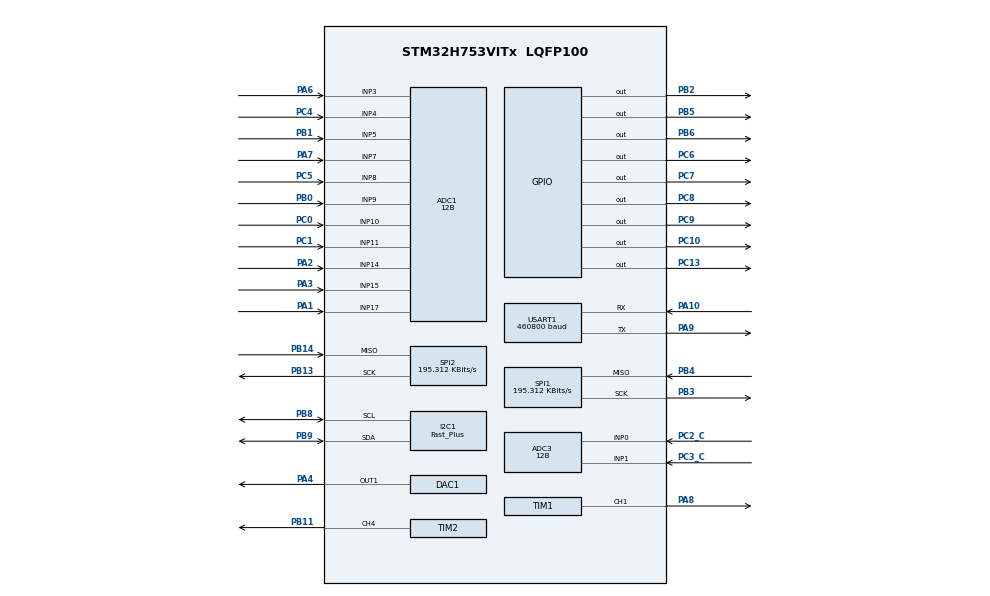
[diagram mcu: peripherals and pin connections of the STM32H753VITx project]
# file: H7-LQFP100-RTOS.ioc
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ADC1.Channel-0\#ChannelRegularConversion=ADC_CHANNEL_3
ADC1.Channel-1\#ChannelRegularConversion=ADC_CHANNEL_4
ADC1.Channel-10\#ChannelRegularConversion=ADC_CHANNEL_17
ADC1.Channel-2\#ChannelRegularConversion=ADC_CHANNEL_5
ADC1.Channel-3\#ChannelRegularConversion=ADC_CHANNEL_7
ADC1.Channel-4\#ChannelRegularConversion=ADC_CHANNEL_8
ADC1.Channel-5\#ChannelRegularConversion=ADC_CHANNEL_9
ADC1.Channel-6\#ChannelRegularConversion=ADC_CHANNEL_10
ADC1.Channel-7\#ChannelRegularConversion=ADC_CHANNEL_11
ADC1.Channel-8\#ChannelRegularConversion=ADC_CHANNEL_14
ADC1.Channel-9\#ChannelRegularConversion=ADC_CHANNEL_15
ADC1.ClockPrescaler=ADC_CLOCK_ASYNC_DIV2
ADC1.ClockPrescalerADC3=ADC_CLOCK_ASYNC_DIV2
ADC1.ContinuousConvMode=ENABLE
ADC1.ConversionDataManagement=ADC_CONVERSIONDATA_DMA_CIRCULAR
ADC1.NbrOfConversion=11
ADC1.NbrOfConversionFlag=1
ADC1.OffsetNumber-0\#ChannelRegularConversion=ADC_OFFSET_NONE
ADC1.OffsetNumber-1\#ChannelRegularConversion=ADC_OFFSET_NONE
ADC1.OffsetNumber-10\#ChannelRegularConversion=ADC_OFFSET_NONE
ADC1.OffsetNumber-2\#ChannelRegularConversion=ADC_OFFSET_NONE
ADC1.OffsetNumber-3\#ChannelRegularConversion=ADC_OFFSET_NONE
ADC1.OffsetNumber-4\#ChannelRegularConversion=ADC_OFFSET_NONE
ADC1.OffsetNumber-5\#ChannelRegularConversion=ADC_OFFSET_NONE
ADC1.OffsetNumber-6\#ChannelRegularConversion=ADC_OFFSET_NONE
ADC1.OffsetNumber-7\#ChannelRegularConversion=ADC_OFFSET_NONE
ADC1.OffsetNumber-8\#ChannelRegularConversion=ADC_OFFSET_NONE
ADC1.OffsetNumber-9\#ChannelRegularConversion=ADC_OFFSET_NONE
ADC1.OffsetSignedSaturation-0\#ChannelRegularConversion=DISABLE
ADC1.Overrun=ADC_OVR_DATA_OVERWRITTEN
ADC1.Rank-0\#ChannelRegularConversion=1
ADC1.Rank-1\#ChannelRegularConversion=2
ADC1.Rank-10\#ChannelRegularConversion=11
ADC1.Rank-2\#ChannelRegularConversion=3
ADC1.Rank-3\#ChannelRegularConversion=4
ADC1.Rank-4\#ChannelRegularConversion=5
ADC1.Rank-5\#ChannelRegularConversion=6
ADC1.Rank-6\#ChannelRegularConversion=7
ADC1.Rank-7\#ChannelRegularConversion=8
ADC1.Rank-8\#ChannelRegularConversion=9
ADC1.Rank-9\#ChannelRegularConversion=10
ADC1.Resolution=ADC_RESOLUTION_12B
ADC1.SamplingTime-0\#ChannelRegularConversion=ADC_SAMPLETIME_810CYCLES_5
ADC1.SamplingTime-1\#ChannelRegularConversion=ADC_SAMPLETIME_810CYCLES_5
ADC1.SamplingTime-10\#ChannelRegularConversion=ADC_SAMPLETIME_810CYCLES_5
ADC1.SamplingTime-2\#ChannelRegularConversion=ADC_SAMPLETIME_810CYCLES_5
ADC1.SamplingTime-3\#ChannelRegularConversion=ADC_SAMPLETIME_810CYCLES_5
ADC1.SamplingTime-4\#ChannelRegularConversion=ADC_SAMPLETIME_810CYCLES_5
ADC1.SamplingTime-5\#ChannelRegularConversion=ADC_SAMPLETIME_810CYCLES_5
ADC1.SamplingTime-6\#ChannelRegularConversion=ADC_SAMPLETIME_810CYCLES_5
ADC1.SamplingTime-7\#ChannelRegularConversion=ADC_SAMPLETIME_810CYCLES_5
ADC1.SamplingTime-8\#ChannelRegularConversion=ADC_SAMPLETIME_810CYCLES_5
ADC1.SamplingTime-9\#ChannelRegularConversion=ADC_SAMPLETIME_810CYCLES_5
ADC1.master=1
ADC3.Channel-0\#ChannelRegularConversion=ADC_CHANNEL_TEMPSENSOR
ADC3.Channel-1\#ChannelRegularConversion=ADC_CHANNEL_VREFINT
ADC3.Channel-2\#ChannelRegularConversion=ADC_CHANNEL_0
ADC3.Channel-3\#ChannelRegularConversion=ADC_CHANNEL_1
ADC3.ClockPrescalerADC3=ADC_CLOCK_ASYNC_DIV2
ADC3.ContinuousConvMode=ENABLE
ADC3.ConversionDataManagement=ADC_CONVERSIONDATA_DMA_CIRCULAR
ADC3.NbrOfConversion=4
ADC3.NbrOfConversionFlag=1
ADC3.OffsetNumber-0\#ChannelRegularConversion=ADC_OFFSET_NONE
ADC3.OffsetNumber-1\#ChannelRegularConversion=ADC_OFFSET_NONE
ADC3.OffsetNumber-2\#ChannelRegularConversion=ADC_OFFSET_NONE
ADC3.OffsetNumber-3\#ChannelRegularConversion=ADC_OFFSET_NONE
ADC3.OffsetSignedSaturation-0\#ChannelRegularConversion=DISABLE
ADC3.Overrun=ADC_OVR_DATA_OVERWRITTEN
ADC3.Rank-0\#ChannelRegularConversion=1
ADC3.Rank-1\#ChannelRegularConversion=2
ADC3.Rank-2\#ChannelRegularConversion=3
ADC3.Rank-3\#ChannelRegularConversion=4
ADC3.Resolution=ADC_RESOLUTION_12B
ADC3.SamplingTime-0\#ChannelRegularConversion=ADC_SAMPLETIME_810CYCLES_5
ADC3.SamplingTime-1\#ChannelRegularConversion=ADC_SAMPLETIME_810CYCLES_5
ADC3.SamplingTime-2\#ChannelRegularConversion=ADC_SAMPLETIME_810CYCLES_5
ADC3.SamplingTime-3\#ChannelRegularConversion=ADC_SAMPLETIME_810CYCLES_5
DAC1.DAC_Channel-DAC_OUT1=DAC_CHANNEL_1
DAC1.DAC_Trigger-DAC_OUT1=DAC_TRIGGER_T2_TRGO
Dma.ADC1.0.Direction=DMA_PERIPH_TO_MEMORY
Dma.ADC1.0.EventEnable=DISABLE
Dma.ADC1.0.FIFOMode=DMA_FIFOMODE_DISABLE
Dma.ADC1.0.Instance=DMA1_Stream0
Dma.ADC1.0.MemDataAlignment=DMA_MDATAALIGN_HALFWORD
Dma.ADC1.0.MemInc=DMA_MINC_ENABLE
Dma.ADC1.0.Mode=DMA_CIRCULAR
Dma.ADC1.0.PeriphDataAlignment=DMA_PDATAALIGN_HALFWORD
Dma.ADC1.0.PeriphInc=DMA_PINC_DISABLE
Dma.ADC1.0.Polarity=HAL_DMAMUX_REQ_GEN_RISING
Dma.ADC1.0.Priority=DMA_PRIORITY_LOW
Dma.ADC1.0.RequestNumber=1
Dma.ADC1.0.SignalID=NONE
Dma.ADC1.0.SyncEnable=DISABLE
Dma.ADC1.0.SyncPolarity=HAL_DMAMUX_SYNC_NO_EVENT
Dma.ADC1.0.SyncRequestNumber=1
Dma.ADC1.0.SyncSignalID=NONE
Dma.ADC3.1.Direction=DMA_PERIPH_TO_MEMORY
Dma.ADC3.1.EventEnable=DISABLE
Dma.ADC3.1.FIFOMode=DMA_FIFOMODE_DISABLE
Dma.ADC3.1.Instance=DMA1_Stream1
Dma.ADC3.1.MemDataAlignment=DMA_MDATAALIGN_HALFWORD
Dma.ADC3.1.MemInc=DMA_MINC_ENABLE
Dma.ADC3.1.Mode=DMA_CIRCULAR
Dma.ADC3.1.PeriphDataAlignment=DMA_PDATAALIGN_HALFWORD
Dma.ADC3.1.PeriphInc=DMA_PINC_DISABLE
Dma.ADC3.1.Polarity=HAL_DMAMUX_REQ_GEN_RISING
Dma.ADC3.1.Priority=DMA_PRIORITY_LOW
Dma.ADC3.1.RequestNumber=1
Dma.ADC3.1.SignalID=NONE
Dma.ADC3.1.SyncEnable=DISABLE
Dma.ADC3.1.SyncPolarity=HAL_DMAMUX_SYNC_NO_EVENT
Dma.ADC3.1.SyncRequestNumber=1
Dma.ADC3.1.SyncSignalID=NONE
Dma.DAC1_CH1.2.Direction=DMA_MEMORY_TO_PERIPH
Dma.DAC1_CH1.2.EventEnable=DISABLE
Dma.DAC1_CH1.2.FIFOMode=DMA_FIFOMODE_DISABLE
Dma.DAC1_CH1.2.Instance=DMA1_Stream5
Dma.DAC1_CH1.2.MemDataAlignment=DMA_MDATAALIGN_WORD
Dma.DAC1_CH1.2.MemInc=DMA_MINC_ENABLE
Dma.DAC1_CH1.2.Mode=DMA_CIRCULAR
Dma.DAC1_CH1.2.PeriphDataAlignment=DMA_PDATAALIGN_WORD
Dma.DAC1_CH1.2.PeriphInc=DMA_PINC_DISABLE
Dma.DAC1_CH1.2.Polarity=HAL_DMAMUX_REQ_GEN_RISING
Dma.DAC1_CH1.2.Priority=DMA_PRIORITY_LOW
Dma.DAC1_CH1.2.RequestNumber=1
Dma.DAC1_CH1.2.SignalID=NONE
Dma.DAC1_CH1.2.SyncEnable=DISABLE
Dma.DAC1_CH1.2.SyncPolarity=HAL_DMAMUX_SYNC_NO_EVENT
Dma.DAC1_CH1.2.SyncRequestNumber=1
Dma.DAC1_CH1.2.SyncSignalID=NONE
Dma.Request0=ADC1
Dma.Request1=ADC3
Dma.Request2=DAC1_CH1
Dma.Request3=USART1_TX
Dma.USART1_TX.3.Direction=DMA_MEMORY_TO_PERIPH
Dma.USART1_TX.3.EventEnable=DISABLE
Dma.USART1_TX.3.FIFOMode=DMA_FIFOMODE_DISABLE
Dma.USART1_TX.3.Instance=DMA1_Stream2
Dma.USART1_TX.3.MemDataAlignment=DMA_MDATAALIGN_BYTE
Dma.USART1_TX.3.MemInc=DMA_MINC_ENABLE
Dma.USART1_TX.3.Mode=DMA_NORMAL
Dma.USART1_TX.3.PeriphDataAlignment=DMA_PDATAALIGN_BYTE
Dma.USART1_TX.3.PeriphInc=DMA_PINC_DISABLE
Dma.USART1_TX.3.Polarity=HAL_DMAMUX_REQ_GEN_RISING
Dma.USART1_TX.3.Priority=DMA_PRIORITY_LOW
Dma.USART1_TX.3.RequestNumber=1
Dma.USART1_TX.3.SignalID=NONE
Dma.USART1_TX.3.SyncEnable=DISABLE
Dma.USART1_TX.3.SyncPolarity=HAL_DMAMUX_SYNC_NO_EVENT
Dma.USART1_TX.3.SyncRequestNumber=1
Dma.USART1_TX.3.SyncSignalID=NONE
FREERTOS.INCLUDE_xEventGroupSetBitFromISR=1
FREERTOS.Tasks01=PMT_task,24,128,PMT_init,Default,NULL,Dynamic,NULL,NULL;ERPA_task,24,128,ERPA_init,Default,NULL,Dynamic,NULL,NULL;HK_task,24,128,HK_init,Default,NULL,Dynamic,NULL,NULL;GPIO_on_task,8,128,GPIO_on_init,Default,NULL,Static,GPIO_on_taskBuffer,GPIO_on_taskControlBlock;GPIO_off_task,8,128,GPIO_off_init,Default,NULL,Static,GPIO_off_taskBuffer,GPIO_off_taskControlBlock;UART_TX_task,8,128,UART_TX_init,Default,NULL,Dynamic,NULL,NULL;Voltage_Monitor,40,128,Voltage_Monitor_init,Default,NULL,Dynamic,NULL,NULL;FLAG_task,8,128,FLAG_init,Default,NULL,Dynamic,NULL,NULL;Science_task,8,128,Science_init,Default,NULL,Dynamic,NULL,NULL;Idle_task,8,128,Idle_init,Default,NULL,Dynamic,NULL,NULL
FREERTOS.configUSE_TICK_HOOK=1
I2C1.I2C_Speed_Mode=I2C_Fast_Plus
I2C1.Timing=0x0020081F
Mcu.Family=STM32H7
Mcu.Name=STM32H753VITx
Mcu.Package=LQFP100
NVIC.DMA1_Stream0_IRQn=true\:5\:0\:false\:false\:true\:true\:false\:true\:true
NVIC.DMA1_Stream1_IRQn=true\:5\:0\:false\:false\:true\:true\:false\:true\:true
NVIC.DMA1_Stream2_IRQn=true\:5\:0\:false\:false\:true\:true\:false\:true\:true
NVIC.DMA1_Stream5_IRQn=true\:5\:0\:false\:false\:true\:false\:false\:true\:true
NVIC.PriorityGroup=NVIC_PRIORITYGROUP_4
NVIC.TIM1_BRK_IRQn=true\:5\:0\:false\:false\:true\:true\:true\:true\:true
NVIC.TIM1_CC_IRQn=true\:5\:0\:false\:false\:true\:true\:true\:true\:true
NVIC.TIM1_TRG_COM_IRQn=true\:5\:0\:false\:false\:true\:true\:true\:true\:true
NVIC.TIM1_UP_IRQn=true\:5\:0\:false\:false\:true\:true\:true\:true\:true
NVIC.TIM2_IRQn=true\:5\:0\:false\:false\:true\:true\:true\:true\:true
NVIC.TIM3_IRQn=true\:5\:0\:false\:false\:true\:true\:true\:true\:true
NVIC.TIM6_DAC_IRQn=true\:5\:0\:true\:false\:true\:false\:false\:true\:true
NVIC.TimeBase=TIM6_DAC_IRQn
NVIC.TimeBaseIP=TIM6
NVIC.USART1_IRQn=true\:5\:0\:false\:false\:true\:true\:true\:true\:true
PA1.Mode=IN17-Single-Ended
PA1.Signal=ADC1_INP17
PA10.Mode=Asynchronous
PA10.Signal=USART1_RX
PA2.Signal=ADCx_INP14
PA3.Signal=ADCx_INP15
PA4.Signal=COMP_DAC11_group
PA6.Signal=ADCx_INP3
PA7.Signal=ADCx_INP7
PA8.Signal=S_TIM1_CH1
PA9.Mode=Asynchronous
PA9.Signal=USART1_TX
PB0.Signal=ADCx_INP9
PB1.Signal=ADCx_INP5
PB11.Signal=S_TIM2_CH4
PB13.Mode=RX_Only_Simplex_Unidirect_Master
PB13.Signal=SPI2_SCK
PB14.Mode=RX_Only_Simplex_Unidirect_Master
PB14.Signal=SPI2_MISO
PB2.GPIO_PuPd=GPIO_PULLDOWN
PB2.Signal=GPIO_Output
PB3\ (JTDO/TRACESWO).Mode=RX_Only_Simplex_Unidirect_Master
PB3\ (JTDO/TRACESWO).Signal=SPI1_SCK
PB4\ (NJTRST).Mode=RX_Only_Simplex_Unidirect_Master
PB4\ (NJTRST).Signal=SPI1_MISO
PB5.GPIO_PuPd=GPIO_PULLDOWN
PB5.Signal=GPIO_Output
PB6.GPIO_PuPd=GPIO_PULLDOWN
PB6.Signal=GPIO_Output
PB8.Mode=I2C
PB8.Signal=I2C1_SCL
PB9.Mode=I2C
PB9.Signal=I2C1_SDA
PC0.Signal=ADCx_INP10
PC1.Signal=ADCx_INP11
PC10.GPIO_PuPd=GPIO_PULLDOWN
PC10.Signal=GPIO_Output
PC13.GPIO_PuPd=GPIO_PULLDOWN
PC13.Signal=GPIO_Output
PC14-OSC32_IN\ (OSC32_IN).Mode=LSE-External-Oscillator
PC14-OSC32_IN\ (OSC32_IN).Signal=RCC_OSC32_IN
PC15-OSC32_OUT\ (OSC32_OUT).Mode=LSE-External-Oscillator
PC15-OSC32_OUT\ (OSC32_OUT).Signal=RCC_OSC32_OUT
PC2_C.Mode=IN0-Single-Ended
PC2_C.Signal=ADC3_INP0
PC3_C.Mode=IN1-Single-Ended
PC3_C.Signal=ADC3_INP1
PC4.Signal=ADCx_INP4
PC5.Signal=ADCx_INP8
PC6.GPIO_PuPd=GPIO_PULLDOWN
PC6.Signal=GPIO_Output
PC7.GPIO_PuPd=GPIO_PULLDOWN
PC7.Signal=GPIO_Output
PC8.GPIO_PuPd=GPIO_PULLDOWN
PC8.Signal=GPIO_Output
PC9.GPIO_PuPd=GPIO_PULLDOWN
PC9.Signal=GPIO_Output
PH0-OSC_IN\ (PH0).Mode=HSE-External-Oscillator
PH0-OSC_IN\ (PH0).Signal=RCC_OSC_IN
PH1-OSC_OUT\ (PH1).Mode=HSE-External-Oscillator
PH1-OSC_OUT\ (PH1).Signal=RCC_OSC_OUT
ProjectManager.HeapSize=0x200
ProjectManager.StackSize=0x400
ProjectManager.TargetToolchain=STM32CubeIDE
RCC.ADCFreq_Value=25000000
RCC.APB1Freq_Value=50000000
RCC.APB2Freq_Value=50000000
RCC.APB3Freq_Value=50000000
RCC.APB4Freq_Value=50000000
RCC.CortexFreq_Value=50000000
RCC.DIVM1=2
RCC.DIVM2=2
RCC.DIVM3=2
RCC.DIVN1=12
RCC.DIVN2=12
RCC.DIVN3=12
RCC.DIVP1=4
RCC.DIVP2=8
RCC.DIVP3=4
RCC.DIVQ1=4
RCC.DIVQ2=4
RCC.DIVQ3=4
RCC.DIVR3=4
RCC.HCLKFreq_Value=50000000
RCC.HSIDiv=RCC_PLLSAIDIVR_2
RCC.PLL2FRACN=4096
RCC.PLL2_VCI_Range-AdvancedSettings=RCC_PLL2VCIRANGE_0
RCC.PLL3FRACN=4096
RCC.PLLFRACN=4096
RCC.ProductRev=revV
RCC.RCC_RTC_Clock_Source_FROM_HSE=RCC_RTCCLKSOURCE_HSE_DIV25
RCC.RTCClockSelection=RCC_RTCCLKSOURCE_HSE_DIV25
RCC.SYSCLKFreq_VALUE=50000000
RCC.SYSCLKSource=RCC_SYSCLKSOURCE_PLLCLK
RCC.USART16CLockSelection=RCC_USART16CLKSOURCE_HSI
RCC.USBFreq_Value=50000000
RTC.AsynchPrediv=100-1
RTC.SynchPrediv=10000-1
SH.ADCx_INP10.0=ADC1_INP10,IN10-Single-Ended
SH.ADCx_INP11.0=ADC1_INP11,IN11-Single-Ended
SH.ADCx_INP14.0=ADC1_INP14,IN14-Single-Ended
SH.ADCx_INP15.0=ADC1_INP15,IN15-Single-Ended
SH.ADCx_INP3.0=ADC1_INP3,IN3-Single-Ended
SH.ADCx_INP4.0=ADC1_INP4,IN4-Single-Ended
SH.ADCx_INP5.0=ADC1_INP5,IN5-Single-Ended
SH.ADCx_INP7.0=ADC1_INP7,IN7-Single-Ended
SH.ADCx_INP8.0=ADC1_INP8,IN8-Single-Ended
SH.ADCx_INP9.0=ADC1_INP9,IN9-Single-Ended
SH.COMP_DAC11_group.0=DAC1_OUT1,DAC_OUT1
SH.S_TIM1_CH1.0=TIM1_CH1,PWM Generation1 CH1
SH.S_TIM2_CH4.0=TIM2_CH4,PWM Generation4 CH4
SPI1.BaudRatePrescaler=SPI_BAUDRATEPRESCALER_256
SPI1.CalculateBaudRate=195.312 KBits/s
SPI1.DataSize=SPI_DATASIZE_16BIT
SPI1.Direction=SPI_DIRECTION_2LINES_RXONLY
SPI1.Mode=SPI_MODE_MASTER
SPI1.VirtualType=VM_MASTER
SPI2.BaudRatePrescaler=SPI_BAUDRATEPRESCALER_256
SPI2.CalculateBaudRate=195.312 KBits/s
SPI2.DataSize=SPI_DATASIZE_16BIT
SPI2.Direction=SPI_DIRECTION_2LINES_RXONLY
SPI2.Mode=SPI_MODE_MASTER
SPI2.VirtualType=VM_MASTER
TIM1.Channel-PWM\ Generation1\ CH1=TIM_CHANNEL_1
TIM1.Period=62500-1
TIM1.Prescaler=50-1
TIM1.Pulse-PWM\ Generation1\ CH1=480-1
TIM2.AutoReloadPreload=TIM_AUTORELOAD_PRELOAD_ENABLE
TIM2.Channel-PWM\ Generation4\ CH4=TIM_CHANNEL_4
TIM2.Period=3125-1
TIM2.Prescaler=50-1
TIM2.TIM_MasterOutputTrigger=TIM_TRGO_UPDATE
TIM3.Period=50000-1
TIM3.Prescaler=100-1
USART1.BaudRate=460800
USART1.VirtualMode-Asynchronous=VM_ASYNC
VP_ADC3_TempSens_Input.Mode=IN-TempSens
VP_ADC3_Vref_Input.Mode=IN-Vrefint
VP_FREERTOS_VS_CMSIS_V2.Mode=CMSIS_V2
VP_RTC_VS_RTC_Activate.Mode=RTC_Enabled
VP_RTC_VS_RTC_Calendar.Mode=RTC_Calendar
VP_SYS_VS_tim6.Mode=TIM6
VP_TIM1_VS_ClockSourceINT.Mode=Internal
VP_TIM2_VS_ClockSourceINT.Mode=Internal
VP_TIM3_VS_ClockSourceINT.Mode=Internal
board=custom

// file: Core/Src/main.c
/* USER CODE BEGIN Header */
/**
 ******************************************************************************
 * @file           : main.c
 * @author 		   : Jared Morrison
 * @version 	   : 2.0.0-alpha
 * @brief          : Main program body
 ******************************************************************************
 * @attention
 *
 * Copyright (c) 2024 STMicroelectronics.
 * All rights reserved.
 *
 * This software is licensed under terms that can be found in the LICENSE file
 * in the root directory of this software component.
 * If no LICENSE file comes with this software, it is provided AS-IS.
 *
 ******************************************************************************
 */
/* USER CODE END Header */
#include "main.h"
#include "cmsis_os.h"

/* USER CODE BEGIN Includes */
#include <stdio.h>
#include <stdlib.h>
#include <string.h>
#include <time.h>
#include "stm32h7xx_hal.h"

/* USER CODE END Includes */

typedef StaticTask_t osStaticThreadDef_t;
/* USER CODE BEGIN PTD */
typedef struct {
	uint8_t *array;  // Pointer to the array data
	uint16_t size;   // Size of the array
} packet_t;

typedef struct {
	GPIO_TypeDef *gpio;
	uint16_t pin;
} gpio_pins;

typedef enum {
	RAIL_vsense,	// 0
	RAIL_vrefint,	// 1
	RAIL_TEMP1,		// 2
	RAIL_TEMP2,		// 3
	RAIL_TEMP3,		// 4
	RAIL_TEMP4,		// 5
	RAIL_busvmon,	// 6
	RAIL_busimon,	// 7
	RAIL_2v5,		// 8
	RAIL_3v3,		// 9
	RAIL_5v,		// 10
	RAIL_n3v3,		// 11
	RAIL_n5v,		// 12
	RAIL_15v,		// 13
	RAIL_5vref,		// 14
	RAIL_n200v,		// 15
	RAIL_n800v,		// 16
	RAIL_TMP1		// 17
} VOLTAGE_RAIL_NAME;

typedef struct {
	VOLTAGE_RAIL_NAME name;
	uint8_t error_count;
	uint8_t is_enabled;
	uint16_t data;
	uint16_t max_voltage;
	uint16_t min_voltage;
} VOLTAGE_RAIL;

/* USER CODE END PTD */

/* USER CODE BEGIN PD */
// *********************************************************************************************************** DEFINES

//#define FLIGHT_MODE

#define PMT_FLAG_ID 0x0001
#define ERPA_FLAG_ID 0x0002
#define HK_FLAG_ID 0x0004
#define VOLTAGE_MONITOR_FLAG_ID 0x0008
#define STOP_FLAG 0x0016

#define PMT_DATA_SIZE 10
#define ERPA_DATA_SIZE 14
#define HK_DATA_SIZE 54
#define UART_RX_BUFFER_SIZE 64
#define UART_TX_BUFFER_SIZE 1000
#define UPTIME_SIZE 4
#define TIMESTAMP_SIZE 10

#define MSGQUEUE_OBJECTS 128
#define ERROR_PACKET_DATA_SIZE 3

#define ADC1_NUM_CHANNELS 11
#define ADC3_NUM_CHANNELS 4

#define PMT_SYNC 0xBB
#define ERPA_SYNC 0xAA
#define HK_SYNC 0xCC
#define ERROR_SYNC 0xDD

#define ACK 0xFF
#define NACK 0x00

#define NUM_VOLTAGE_RAILS 18
/* USER CODE END PD */

ADC_HandleTypeDef hadc1;
ADC_HandleTypeDef hadc3;
DMA_HandleTypeDef hdma_adc1;
DMA_HandleTypeDef hdma_adc3;

DAC_HandleTypeDef hdac1;
DMA_HandleTypeDef hdma_dac1_ch1;

I2C_HandleTypeDef hi2c1;

RTC_HandleTypeDef hrtc;

SPI_HandleTypeDef hspi1;
SPI_HandleTypeDef hspi2;

TIM_HandleTypeDef htim1;
TIM_HandleTypeDef htim2;
TIM_HandleTypeDef htim3;

UART_HandleTypeDef huart1;
DMA_HandleTypeDef hdma_usart1_tx;

/* Definitions for PMT_task */
osThreadId_t PMT_taskHandle;
const osThreadAttr_t PMT_task_attributes = {
  .name = "PMT_task",
  .stack_size = 128 * 4,
  .priority = (osPriority_t) osPriorityNormal,
};
/* Definitions for ERPA_task */
osThreadId_t ERPA_taskHandle;
const osThreadAttr_t ERPA_task_attributes = {
  .name = "ERPA_task",
  .stack_size = 128 * 4,
  .priority = (osPriority_t) osPriorityNormal,
};
/* Definitions for HK_task */
osThreadId_t HK_taskHandle;
const osThreadAttr_t HK_task_attributes = {
  .name = "HK_task",
  .stack_size = 128 * 4,
  .priority = (osPriority_t) osPriorityNormal,
};
/* Definitions for GPIO_on_task */
osThreadId_t GPIO_on_taskHandle;
uint32_t GPIO_on_taskBuffer[ 128 ];
osStaticThreadDef_t GPIO_on_taskControlBlock;
const osThreadAttr_t GPIO_on_task_attributes = {
  .name = "GPIO_on_task",
  .cb_mem = &GPIO_on_taskControlBlock,
  .cb_size = sizeof(GPIO_on_taskControlBlock),
  .stack_mem = &GPIO_on_taskBuffer[0],
  .stack_size = sizeof(GPIO_on_taskBuffer),
  .priority = (osPriority_t) osPriorityLow,
};
/* Definitions for GPIO_off_task */
osThreadId_t GPIO_off_taskHandle;
uint32_t GPIO_off_taskBuffer[ 128 ];
osStaticThreadDef_t GPIO_off_taskControlBlock;
const osThreadAttr_t GPIO_off_task_attributes = {
  .name = "GPIO_off_task",
  .cb_mem = &GPIO_off_taskControlBlock,
  .cb_size = sizeof(GPIO_off_taskControlBlock),
  .stack_mem = &GPIO_off_taskBuffer[0],
  .stack_size = sizeof(GPIO_off_taskBuffer),
  .priority = (osPriority_t) osPriorityLow,
};
/* Definitions for UART_TX_task */
osThreadId_t UART_TX_taskHandle;
const osThreadAttr_t UART_TX_task_attributes = {
  .name = "UART_TX_task",
  .stack_size = 128 * 4,
  .priority = (osPriority_t) osPriorityLow,
};
/* Definitions for Voltage_Monitor */
osThreadId_t Voltage_MonitorHandle;
const osThreadAttr_t Voltage_Monitor_attributes = {
  .name = "Voltage_Monitor",
  .stack_size = 128 * 4,
  .priority = (osPriority_t) osPriorityHigh,
};
/* Definitions for FLAG_task */
osThreadId_t FLAG_taskHandle;
const osThreadAttr_t FLAG_task_attributes = {
  .name = "FLAG_task",
  .stack_size = 128 * 4,
  .priority = (osPriority_t) osPriorityLow,
};
/* Definitions for Science_task */
osThreadId_t Science_taskHandle;
const osThreadAttr_t Science_task_attributes = {
  .name = "Science_task",
  .stack_size = 128 * 4,
  .priority = (osPriority_t) osPriorityLow,
};
/* Definitions for Idle_task */
osThreadId_t Idle_taskHandle;
const osThreadAttr_t Idle_task_attributes = {
  .name = "Idle_task",
  .stack_size = 128 * 4,
  .priority = (osPriority_t) osPriorityLow,
};
/* USER CODE BEGIN PV */
// *********************************************************************************************************** GLOBAL VARIABLES
VOLTAGE_RAIL rail_monitor[NUM_VOLTAGE_RAILS];

volatile uint8_t HK_10_second_counter = 0;
volatile uint32_t uptime_millis = 0;
osMessageQueueId_t mid_MsgQueue;
packet_t msg;

volatile int tx_flag = 1;

uint16_t pmt_seq = 0;
uint32_t erpa_seq = 0;
uint16_t hk_seq = 0;

volatile uint8_t PMT_ON = 0;
volatile uint8_t ERPA_ON = 0;
volatile uint8_t HK_ON = 0;

volatile uint32_t cadence = 3125;
volatile uint8_t step = 3;

osEventFlagsId_t event_flags;

unsigned char UART_RX_BUFFER[UART_RX_BUFFER_SIZE];

ALIGN_32BYTES(static uint16_t ADC1_raw_data[ADC1_NUM_CHANNELS]);
ALIGN_32BYTES(static uint16_t ADC3_raw_data[ADC3_NUM_CHANNELS]);

static const uint8_t REG_TEMP = 0x00;
static const uint8_t ADT7410_1 = 0x48 << 1;
static const uint8_t ADT7410_2 = 0x4A << 1;
static const uint8_t ADT7410_3 = 0x49 << 1;
static const uint8_t ADT7410_4 = 0x4B << 1;

uint32_t DAC_OUT[32] = { 0, 0, 620, 620, 1241, 1241, 1861, 1861, 2482, 2482,
		3103, 3103, 3723, 3723, 4095, 4095, 4095, 4095, 3723, 3723, 3103, 3103,
		2482, 2482, 1861, 1861, 1241, 1241, 620, 620, 0, 0 }; // For 3.3 volts

const gpio_pins gpios[] = {
{ GPIOB, GPIO_PIN_2 },	// 0 -- SDN1
{ GPIOB, GPIO_PIN_5 },	// 1 -- SYS_ON
{ GPIOC, GPIO_PIN_10 },	// 2 -- 3v3_EN
{ GPIOC, GPIO_PIN_7 },	// 3 -- 5v_EN
{ GPIOC, GPIO_PIN_6 },	// 4 -- N3V3_EN
{ GPIOC, GPIO_PIN_8 },	// 5 -- N5V_EN
{ GPIOC, GPIO_PIN_9 },	// 6 -- 15V_EN
{ GPIOC, GPIO_PIN_13 },	// 7 -- N150V_EN
{ GPIOB, GPIO_PIN_6 }	// 8 -- 800HVON
};
/* USER CODE END PV */

void SystemClock_Config(void);
void PeriphCommonClock_Config(void);
static void MX_GPIO_Init(void);
static void MX_DMA_Init(void);
static void MX_TIM3_Init(void);
static void MX_USART1_UART_Init(void);
static void MX_I2C1_Init(void);
static void MX_SPI2_Init(void);
static void MX_TIM2_Init(void);
static void MX_TIM1_Init(void);
static void MX_ADC3_Init(void);
static void MX_ADC1_Init(void);
static void MX_DAC1_Init(void);
static void MX_SPI1_Init(void);
static void MX_RTC_Init(void);
void PMT_init(void *argument);
void ERPA_init(void *argument);
void HK_init(void *argument);
void GPIO_on_init(void *argument);
void GPIO_off_init(void *argument);
void UART_TX_init(void *argument);
void Voltage_Monitor_init(void *argument);
void FLAG_init(void *argument);
void Science_init(void *argument);
void Idle_init(void *argument);

/* USER CODE BEGIN PFP */
// *********************************************************************************************************** FUNCTION PROTOYPES
void system_setup();
int in_range(uint16_t raw, int min, int max);
void error_protocol(VOLTAGE_RAIL_NAME failed_rail);
packet_t create_packet(const uint8_t *data, uint16_t size);
void sample_hk();
void get_uptime(uint8_t *buffer);
void send_ACK();
void send_NACK();
void sync();
void enter_stop();
uint8_t get_current_step();
void flush_message_queue();
HAL_StatusTypeDef RTC_SetTime(RTC_HandleTypeDef *hrtc, RTC_TimeTypeDef *sTime,
		uint32_t Format);
/* USER CODE END PFP */

/* USER CODE BEGIN 0 */
// *********************************************************************************************************** CALLBACKS
/**
 * @brief Handles the callback for timer delay elapsed events.
 *
 * This function is called when a timer's delay has elapsed and performs
 * specific actions based on the timer instance.
 *
 * @param htim Pointer to the timer handle structure.
 *             Supported timer instances are htim1, htim2, and htim3.
 */
void HAL_TIM_OC_DelayElapsedCallback(TIM_HandleTypeDef *htim) {
	if (htim == &htim1) {
		osEventFlagsSet(event_flags, PMT_FLAG_ID);
	} else if (htim == &htim2) {
		osEventFlagsSet(event_flags, ERPA_FLAG_ID);
	} else if (htim == &htim3) {
		osEventFlagsSet(event_flags, VOLTAGE_MONITOR_FLAG_ID);

// - If flight mode is defined, we only create HK packets every 100 interrupts of TIM3 (running at 100ms)
// - Otherwise, we create HK packets every time TIM3 interrupts
#ifdef FLIGHT_MODE
		if (HK_10_second_counter == 100) {
			osEventFlagsSet(event_flags, HK_FLAG_ID);
			HK_10_second_counter = 0;
		}
		HK_10_second_counter++;
#else
		osEventFlagsSet(event_flags, HK_FLAG_ID);
#endif

	} else {
		printf("Unknown Timer Interrupt\n");
	}
}

/**
 * @brief UART receive complete callback.
 *
 * This function is called when a UART receive operation is complete. It handles
 * various commands received via UART and performs corresponding actions, such as
 * toggling GPIO pins, starting or stopping timers, and other operations.
 *
 * @param huart Pointer to a UART_HandleTypeDef structure that contains
 *              the configuration information for the specified UART module.
 */

void HAL_UART_RxCpltCallback(UART_HandleTypeDef *huart) {
	HAL_UART_Receive_IT(&huart1, UART_RX_BUFFER, 1);
	unsigned char key = UART_RX_BUFFER[0];

	switch (key) {
	case 0x10: {
		printf("SDN1 ON\n");
		HAL_GPIO_WritePin(gpios[0].gpio, gpios[0].pin, GPIO_PIN_SET);
		break;
	}
	case 0x00: {
		printf("SDN1 OFF\n");
		HAL_GPIO_WritePin(gpios[0].gpio, gpios[0].pin, GPIO_PIN_RESET);
		break;
	}
	case 0x11: {
		printf("SYS ON PB5\n");
		HAL_GPIO_WritePin(gpios[1].gpio, gpios[1].pin, GPIO_PIN_SET);
		rail_monitor[RAIL_2v5].is_enabled = 1;
		break;
	}
	case 0x01: {
		printf("SYS OFF PB5\n");

		// Turning off all voltage enables (including high voltages) in order from highest to lowest, including SYS_ON
		for (int i = 8; i > 0; i--) {
			HAL_GPIO_WritePin(gpios[i].gpio, gpios[i].pin, GPIO_PIN_RESET);
			rail_monitor[i].is_enabled = 0;
		}

		break;
	}
	case 0x12: {
		printf("3v3 ON PC10\n");
		HAL_GPIO_WritePin(gpios[2].gpio, gpios[2].pin, GPIO_PIN_SET);
		rail_monitor[RAIL_3v3].is_enabled = 1;

		break;
	}
	case 0x02: {
		printf("3v3 OFF PC10\n");
		HAL_GPIO_WritePin(gpios[2].gpio, gpios[2].pin, GPIO_PIN_RESET);
		rail_monitor[RAIL_3v3].is_enabled = 0;
		break;
	}
	case 0x13: {
		printf("5v ON PC7\n");
		HAL_GPIO_WritePin(gpios[3].gpio, gpios[3].pin, GPIO_PIN_SET);
		rail_monitor[RAIL_5v].is_enabled = 1;
		break;
	}
	case 0x03: {
		printf("5v OFF PC7\n");
		HAL_GPIO_WritePin(gpios[3].gpio, gpios[3].pin, GPIO_PIN_RESET);
		rail_monitor[RAIL_5v].is_enabled = 0;
		break;
	}
	case 0x14: {
		printf("n3v3 ON PC6\n");
		HAL_GPIO_WritePin(gpios[4].gpio, gpios[4].pin, GPIO_PIN_SET);
		rail_monitor[RAIL_n3v3].is_enabled = 1;
		break;
	}
	case 0x04: {
		printf("n3v3 OFF PC6\n");
		HAL_GPIO_WritePin(gpios[4].gpio, gpios[4].pin, GPIO_PIN_RESET);
		rail_monitor[RAIL_n3v3].is_enabled = 0;
		break;
	}
	case 0x15: {
		printf("n5v ON PC8\n");
		HAL_GPIO_WritePin(gpios[5].gpio, gpios[5].pin, GPIO_PIN_SET);
		rail_monitor[RAIL_n5v].is_enabled = 1;
		break;
	}
	case 0x05: {
		printf("n5v OFF PC8\n");
		HAL_GPIO_WritePin(gpios[5].gpio, gpios[5].pin, GPIO_PIN_RESET);
		rail_monitor[RAIL_n5v].is_enabled = 0;
		break;
	}
	case 0x16: {
		printf("15v ON PC9\n");
		HAL_GPIO_WritePin(gpios[6].gpio, gpios[6].pin, GPIO_PIN_SET);
		rail_monitor[RAIL_15v].is_enabled = 1;
		break;
	}
	case 0x06: {
		printf("15v OFF PC9\n");
		HAL_GPIO_WritePin(gpios[6].gpio, gpios[6].pin, GPIO_PIN_RESET);
		rail_monitor[RAIL_15v].is_enabled = 0;
		break;
	}
	case 0x17: {
		printf("n200v ON PC13\n");
		HAL_GPIO_WritePin(gpios[7].gpio, gpios[7].pin, GPIO_PIN_SET);
		rail_monitor[RAIL_n200v].is_enabled = 1;
		break;
	}
	case 0x07: {
		printf("n200v OFF PC13\n");
		HAL_GPIO_WritePin(gpios[7].gpio, gpios[7].pin, GPIO_PIN_RESET);
		rail_monitor[RAIL_n200v].is_enabled = 0;
		break;
	}
	case 0x18: {
		printf("800v ON PB6\n");
		HAL_GPIO_WritePin(gpios[8].gpio, gpios[8].pin, GPIO_PIN_SET);
		rail_monitor[RAIL_n800v].is_enabled = 1;
		break;
	}
	case 0x08: {
		printf("800v OFF PB6\n");
		HAL_GPIO_WritePin(gpios[8].gpio, gpios[8].pin, GPIO_PIN_RESET);
		rail_monitor[RAIL_n800v].is_enabled = 0;
		break;
	}
	case 0x19: {
		printf("AUTOSWEEP ON\n");
		HAL_DAC_Start_DMA(&hdac1, DAC_CHANNEL_1, DAC_OUT, 32, DAC_ALIGN_12B_R);
		break;
	}
	case 0x09: {
		printf("AUTOSWEEP OFF\n");
		HAL_DAC_Stop_DMA(&hdac1, DAC_CHANNEL_1);
		break;
	}
	case 0x1A: {
		printf("ERPA ON\n");
		HAL_TIM_OC_Start_IT(&htim2, TIM_CHANNEL_4);
		osEventFlagsSet(event_flags, ERPA_FLAG_ID);
		ERPA_ON = 1;
		break;
	}
	case 0x0A: {
		printf("ERPA OFF\n");
		HAL_TIM_OC_Stop_IT(&htim2, TIM_CHANNEL_4);
		ERPA_ON = 0;
		break;
	}
	case 0x1B: {
		printf("PMT ON\n");
		HAL_TIM_OC_Start_IT(&htim1, TIM_CHANNEL_1);
		osEventFlagsSet(event_flags, PMT_FLAG_ID);
		PMT_ON = 1;
		break;
	}
	case 0x0B: {
		printf("PMT OFF\n");
		HAL_TIM_OC_Stop_IT(&htim1, TIM_CHANNEL_1);
		PMT_ON = 0;
		break;
	}
	case 0x1C: {
		printf("HK ON \n");
		osEventFlagsSet(event_flags, HK_FLAG_ID);
		HK_ON = 1;
		break;
	}
	case 0x0C: {
		printf("HK OFF\n");
		HK_ON = 0;
		break;
	}
	case 0x1D: {
		printf("Step Up\n");
		if (step < 17) {
			step += 2;
			HAL_DAC_SetValue(&hdac1, DAC_CHANNEL_1, DAC_ALIGN_12B_R,
					DAC_OUT[step]);
			HAL_DAC_Start(&hdac1, DAC_CHANNEL_1);
		}
		break;
	}
	case 0x0D: {
		printf("Step Down\n");
		if (step > 3) {
			step -= 2;
			HAL_DAC_SetValue(&hdac1, DAC_CHANNEL_1, DAC_ALIGN_12B_R,
					DAC_OUT[step]);
			HAL_DAC_Start(&hdac1, DAC_CHANNEL_1);
		}
		break;
	}
	case 0x1E: {
		printf("Factor Up\n");
		if (cadence <= 50000) {
			cadence *= 2;
			TIM2->ARR = cadence;
		}
		break;
	}
	case 0x0E: {
		printf("Factor Down\n");
		if (cadence >= 6250) {
			cadence /= 2;
			TIM2->ARR = cadence;
		}
		break;
	}
	case 0x0F: {
		printf("Enter STOP mode\n");
		osEventFlagsSet(event_flags, STOP_FLAG);
		break;
	}
	case 0xE0: {
		printf("Auto Init\n");
		xTaskResumeFromISR(GPIO_on_taskHandle);
		break;
	}
	case 0xD0: {
		printf("Auto Deinit\n");
		xTaskResumeFromISR(GPIO_off_taskHandle);
		break;
	}
	case 0xAF: {
		sync();
		break;
	}
	case 0xBF: {
		xTaskResumeFromISR(Science_taskHandle);
		break;
	}
	case 0xCF: {
		xTaskResumeFromISR(Idle_taskHandle);
		break;
	}
	default: {
		printf("Unknown Command\n");
		break;
	}
	}
}
/* USER CODE END 0 */

int main(void)
{

  /* MCU Configuration--------------------------------------------------------*/

  /* Reset of all peripherals, Initializes the Flash interface and the Systick. */
  HAL_Init();

  /* Configure the system clock */
  SystemClock_Config();

/* Configure the peripherals common clocks */
  PeriphCommonClock_Config();

  /* Initialize all configured peripherals */
  MX_GPIO_Init();
  MX_DMA_Init();
  MX_TIM3_Init();
  MX_USART1_UART_Init();
  MX_I2C1_Init();
  MX_SPI2_Init();
  MX_TIM2_Init();
  MX_TIM1_Init();
  MX_ADC3_Init();
  MX_ADC1_Init();
  MX_DAC1_Init();
  MX_SPI1_Init();
  MX_RTC_Init();

  /* Init scheduler */
  osKernelInitialize();

  /* USER CODE BEGIN RTOS_QUEUES */
	/* add queues, ... */
	mid_MsgQueue = osMessageQueueNew(MSGQUEUE_OBJECTS, sizeof(packet_t), NULL);
	if (mid_MsgQueue == NULL) {
		; // Message Queue object not created, handle failure
	}

  /* USER CODE END RTOS_QUEUES */

  /* Create the thread(s) */
  /* creation of PMT_task */
  PMT_taskHandle = osThreadNew(PMT_init, NULL, &PMT_task_attributes);

  /* creation of ERPA_task */
  ERPA_taskHandle = osThreadNew(ERPA_init, NULL, &ERPA_task_attributes);

  /* creation of HK_task */
  HK_taskHandle = osThreadNew(HK_init, NULL, &HK_task_attributes);

  /* creation of GPIO_on_task */
  GPIO_on_taskHandle = osThreadNew(GPIO_on_init, NULL, &GPIO_on_task_attributes);

  /* creation of GPIO_off_task */
  GPIO_off_taskHandle = osThreadNew(GPIO_off_init, NULL, &GPIO_off_task_attributes);

  /* creation of UART_TX_task */
  UART_TX_taskHandle = osThreadNew(UART_TX_init, NULL, &UART_TX_task_attributes);

  /* creation of Voltage_Monitor */
  Voltage_MonitorHandle = osThreadNew(Voltage_Monitor_init, NULL, &Voltage_Monitor_attributes);

  /* creation of FLAG_task */
  FLAG_taskHandle = osThreadNew(FLAG_init, NULL, &FLAG_task_attributes);

  /* creation of Science_task */
  Science_taskHandle = osThreadNew(Science_init, NULL, &Science_task_attributes);

  /* creation of Idle_task */
  Idle_taskHandle = osThreadNew(Idle_init, NULL, &Idle_task_attributes);

  /* USER CODE BEGIN RTOS_EVENTS */
	/* add events, ... */
	event_flags = osEventFlagsNew(NULL);
	system_setup();
	printf("Starting kernal...\n");

  /* USER CODE END RTOS_EVENTS */

  /* Start scheduler */
  osKernelStart();
  /* We should never get here as control is now taken by the scheduler */
  /* Infinite loop */
	while (1) {

	}
}

void SystemClock_Config(void)
{
  RCC_OscInitTypeDef RCC_OscInitStruct = {0};
  RCC_ClkInitTypeDef RCC_ClkInitStruct = {0};

  /** Supply configuration update enable
  */
  HAL_PWREx_ConfigSupply(PWR_LDO_SUPPLY);

  /** Configure the main internal regulator output voltage
  */
  __HAL_PWR_VOLTAGESCALING_CONFIG(PWR_REGULATOR_VOLTAGE_SCALE3);

  while(!__HAL_PWR_GET_FLAG(PWR_FLAG_VOSRDY)) {}

  /** Initializes the RCC Oscillators according to the specified parameters
  * in the RCC_OscInitTypeDef structure.
  */
  RCC_OscInitStruct.OscillatorType = RCC_OSCILLATORTYPE_HSI|RCC_OSCILLATORTYPE_HSE;
  RCC_OscInitStruct.HSEState = RCC_HSE_ON;
  RCC_OscInitStruct.HSIState = RCC_HSI_DIV2;
  RCC_OscInitStruct.HSICalibrationValue = RCC_HSICALIBRATION_DEFAULT;
  RCC_OscInitStruct.PLL.PLLState = RCC_PLL_ON;
  RCC_OscInitStruct.PLL.PLLSource = RCC_PLLSOURCE_HSI;
  RCC_OscInitStruct.PLL.PLLM = 2;
  RCC_OscInitStruct.PLL.PLLN = 12;
  RCC_OscInitStruct.PLL.PLLP = 4;
  RCC_OscInitStruct.PLL.PLLQ = 4;
  RCC_OscInitStruct.PLL.PLLR = 2;
  RCC_OscInitStruct.PLL.PLLRGE = RCC_PLL1VCIRANGE_3;
  RCC_OscInitStruct.PLL.PLLVCOSEL = RCC_PLL1VCOWIDE;
  RCC_OscInitStruct.PLL.PLLFRACN = 4096;
  if (HAL_RCC_OscConfig(&RCC_OscInitStruct) != HAL_OK)
  {
    Error_Handler();
  }

  /** Initializes the CPU, AHB and APB buses clocks
  */
  RCC_ClkInitStruct.ClockType = RCC_CLOCKTYPE_HCLK|RCC_CLOCKTYPE_SYSCLK
                              |RCC_CLOCKTYPE_PCLK1|RCC_CLOCKTYPE_PCLK2
                              |RCC_CLOCKTYPE_D3PCLK1|RCC_CLOCKTYPE_D1PCLK1;
  RCC_ClkInitStruct.SYSCLKSource = RCC_SYSCLKSOURCE_PLLCLK;
  RCC_ClkInitStruct.SYSCLKDivider = RCC_SYSCLK_DIV1;
  RCC_ClkInitStruct.AHBCLKDivider = RCC_HCLK_DIV1;
  RCC_ClkInitStruct.APB3CLKDivider = RCC_APB3_DIV1;
  RCC_ClkInitStruct.APB1CLKDivider = RCC_APB1_DIV1;
  RCC_ClkInitStruct.APB2CLKDivider = RCC_APB2_DIV1;
  RCC_ClkInitStruct.APB4CLKDivider = RCC_APB4_DIV1;

  if (HAL_RCC_ClockConfig(&RCC_ClkInitStruct, FLASH_LATENCY_1) != HAL_OK)
  {
    Error_Handler();
  }
}

void PeriphCommonClock_Config(void)
{
  RCC_PeriphCLKInitTypeDef PeriphClkInitStruct = {0};

  /** Initializes the peripherals clock
  */
  PeriphClkInitStruct.PeriphClockSelection = RCC_PERIPHCLK_ADC;
  PeriphClkInitStruct.PLL2.PLL2M = 2;
  PeriphClkInitStruct.PLL2.PLL2N = 12;
  PeriphClkInitStruct.PLL2.PLL2P = 8;
  PeriphClkInitStruct.PLL2.PLL2Q = 4;
  PeriphClkInitStruct.PLL2.PLL2R = 2;
  PeriphClkInitStruct.PLL2.PLL2RGE = RCC_PLL2VCIRANGE_3;
  PeriphClkInitStruct.PLL2.PLL2VCOSEL = RCC_PLL2VCOWIDE;
  PeriphClkInitStruct.PLL2.PLL2FRACN = 4096;
  PeriphClkInitStruct.AdcClockSelection = RCC_ADCCLKSOURCE_PLL2;
  if (HAL_RCCEx_PeriphCLKConfig(&PeriphClkInitStruct) != HAL_OK)
  {
    Error_Handler();
  }
}

static void MX_ADC1_Init(void)
{

  ADC_MultiModeTypeDef multimode = {0};
  ADC_ChannelConfTypeDef sConfig = {0};

  /** Common config
  */
  hadc1.Instance = ADC1;
  hadc1.Init.ClockPrescaler = ADC_CLOCK_ASYNC_DIV2;
  hadc1.Init.Resolution = ADC_RESOLUTION_12B;
  hadc1.Init.ScanConvMode = ADC_SCAN_ENABLE;
  hadc1.Init.EOCSelection = ADC_EOC_SINGLE_CONV;
  hadc1.Init.LowPowerAutoWait = DISABLE;
  hadc1.Init.ContinuousConvMode = ENABLE;
  hadc1.Init.NbrOfConversion = 11;
  hadc1.Init.DiscontinuousConvMode = DISABLE;
  hadc1.Init.ExternalTrigConv = ADC_SOFTWARE_START;
  hadc1.Init.ExternalTrigConvEdge = ADC_EXTERNALTRIGCONVEDGE_NONE;
  hadc1.Init.ConversionDataManagement = ADC_CONVERSIONDATA_DMA_CIRCULAR;
  hadc1.Init.Overrun = ADC_OVR_DATA_OVERWRITTEN;
  hadc1.Init.LeftBitShift = ADC_LEFTBITSHIFT_NONE;
  hadc1.Init.OversamplingMode = DISABLE;
  if (HAL_ADC_Init(&hadc1) != HAL_OK)
  {
    Error_Handler();
  }

  /** Configure the ADC multi-mode
  */
  multimode.Mode = ADC_MODE_INDEPENDENT;
  if (HAL_ADCEx_MultiModeConfigChannel(&hadc1, &multimode) != HAL_OK)
  {
    Error_Handler();
  }

  /** Configure Regular Channel
  */
  sConfig.Channel = ADC_CHANNEL_3;
  sConfig.Rank = ADC_REGULAR_RANK_1;
  sConfig.SamplingTime = ADC_SAMPLETIME_810CYCLES_5;
  sConfig.SingleDiff = ADC_SINGLE_ENDED;
  sConfig.OffsetNumber = ADC_OFFSET_NONE;
  sConfig.Offset = 0;
  sConfig.OffsetSignedSaturation = DISABLE;
  if (HAL_ADC_ConfigChannel(&hadc1, &sConfig) != HAL_OK)
  {
    Error_Handler();
  }

  /** Configure Regular Channel
  */
  sConfig.Channel = ADC_CHANNEL_4;
  sConfig.Rank = ADC_REGULAR_RANK_2;
  if (HAL_ADC_ConfigChannel(&hadc1, &sConfig) != HAL_OK)
  {
    Error_Handler();
  }

  /** Configure Regular Channel
  */
  sConfig.Channel = ADC_CHANNEL_5;
  sConfig.Rank = ADC_REGULAR_RANK_3;
  if (HAL_ADC_ConfigChannel(&hadc1, &sConfig) != HAL_OK)
  {
    Error_Handler();
  }

  /** Configure Regular Channel
  */
  sConfig.Channel = ADC_CHANNEL_7;
  sConfig.Rank = ADC_REGULAR_RANK_4;
  if (HAL_ADC_ConfigChannel(&hadc1, &sConfig) != HAL_OK)
  {
    Error_Handler();
  }

  /** Configure Regular Channel
  */
  sConfig.Channel = ADC_CHANNEL_8;
  sConfig.Rank = ADC_REGULAR_RANK_5;
  if (HAL_ADC_ConfigChannel(&hadc1, &sConfig) != HAL_OK)
  {
    Error_Handler();
  }

  /** Configure Regular Channel
  */
  sConfig.Channel = ADC_CHANNEL_9;
  sConfig.Rank = ADC_REGULAR_RANK_6;
  if (HAL_ADC_ConfigChannel(&hadc1, &sConfig) != HAL_OK)
  {
    Error_Handler();
  }

  /** Configure Regular Channel
  */
  sConfig.Channel = ADC_CHANNEL_10;
  sConfig.Rank = ADC_REGULAR_RANK_7;
  if (HAL_ADC_ConfigChannel(&hadc1, &sConfig) != HAL_OK)
  {
    Error_Handler();
  }

  /** Configure Regular Channel
  */
  sConfig.Channel = ADC_CHANNEL_11;
  sConfig.Rank = ADC_REGULAR_RANK_8;
  if (HAL_ADC_ConfigChannel(&hadc1, &sConfig) != HAL_OK)
  {
    Error_Handler();
  }

  /** Configure Regular Channel
  */
  sConfig.Channel = ADC_CHANNEL_14;
  sConfig.Rank = ADC_REGULAR_RANK_9;
  if (HAL_ADC_ConfigChannel(&hadc1, &sConfig) != HAL_OK)
  {
    Error_Handler();
  }

  /** Configure Regular Channel
  */
  sConfig.Channel = ADC_CHANNEL_15;
  sConfig.Rank = ADC_REGULAR_RANK_10;
  if (HAL_ADC_ConfigChannel(&hadc1, &sConfig) != HAL_OK)
  {
    Error_Handler();
  }

  /** Configure Regular Channel
  */
  sConfig.Channel = ADC_CHANNEL_17;
  sConfig.Rank = ADC_REGULAR_RANK_11;
  if (HAL_ADC_ConfigChannel(&hadc1, &sConfig) != HAL_OK)
  {
    Error_Handler();
  }

}

static void MX_ADC3_Init(void)
{

  ADC_ChannelConfTypeDef sConfig = {0};

  /** Common config
  */
  hadc3.Instance = ADC3;
  hadc3.Init.Resolution = ADC_RESOLUTION_12B;
  hadc3.Init.ScanConvMode = ADC_SCAN_ENABLE;
  hadc3.Init.EOCSelection = ADC_EOC_SINGLE_CONV;
  hadc3.Init.LowPowerAutoWait = DISABLE;
  hadc3.Init.ContinuousConvMode = ENABLE;
  hadc3.Init.NbrOfConversion = 4;
  hadc3.Init.DiscontinuousConvMode = DISABLE;
  hadc3.Init.ExternalTrigConv = ADC_SOFTWARE_START;
  hadc3.Init.ExternalTrigConvEdge = ADC_EXTERNALTRIGCONVEDGE_NONE;
  hadc3.Init.ConversionDataManagement = ADC_CONVERSIONDATA_DMA_CIRCULAR;
  hadc3.Init.Overrun = ADC_OVR_DATA_OVERWRITTEN;
  hadc3.Init.LeftBitShift = ADC_LEFTBITSHIFT_NONE;
  hadc3.Init.OversamplingMode = DISABLE;
  if (HAL_ADC_Init(&hadc3) != HAL_OK)
  {
    Error_Handler();
  }

  /** Configure Regular Channel
  */
  sConfig.Channel = ADC_CHANNEL_TEMPSENSOR;
  sConfig.Rank = ADC_REGULAR_RANK_1;
  sConfig.SamplingTime = ADC_SAMPLETIME_810CYCLES_5;
  sConfig.SingleDiff = ADC_SINGLE_ENDED;
  sConfig.OffsetNumber = ADC_OFFSET_NONE;
  sConfig.Offset = 0;
  sConfig.OffsetSignedSaturation = DISABLE;
  if (HAL_ADC_ConfigChannel(&hadc3, &sConfig) != HAL_OK)
  {
    Error_Handler();
  }

  /** Configure Regular Channel
  */
  sConfig.Channel = ADC_CHANNEL_VREFINT;
  sConfig.Rank = ADC_REGULAR_RANK_2;
  if (HAL_ADC_ConfigChannel(&hadc3, &sConfig) != HAL_OK)
  {
    Error_Handler();
  }

  /** Configure Regular Channel
  */
  sConfig.Channel = ADC_CHANNEL_0;
  sConfig.Rank = ADC_REGULAR_RANK_3;
  if (HAL_ADC_ConfigChannel(&hadc3, &sConfig) != HAL_OK)
  {
    Error_Handler();
  }

  /** Configure Regular Channel
  */
  sConfig.Channel = ADC_CHANNEL_1;
  sConfig.Rank = ADC_REGULAR_RANK_4;
  if (HAL_ADC_ConfigChannel(&hadc3, &sConfig) != HAL_OK)
  {
    Error_Handler();
  }

}

static void MX_DAC1_Init(void)
{

  DAC_ChannelConfTypeDef sConfig = {0};

  /** DAC Initialization
  */
  hdac1.Instance = DAC1;
  if (HAL_DAC_Init(&hdac1) != HAL_OK)
  {
    Error_Handler();
  }

  /** DAC channel OUT1 config
  */
  sConfig.DAC_SampleAndHold = DAC_SAMPLEANDHOLD_DISABLE;
  sConfig.DAC_Trigger = DAC_TRIGGER_T2_TRGO;
  sConfig.DAC_OutputBuffer = DAC_OUTPUTBUFFER_ENABLE;
  sConfig.DAC_ConnectOnChipPeripheral = DAC_CHIPCONNECT_DISABLE;
  sConfig.DAC_UserTrimming = DAC_TRIMMING_FACTORY;
  if (HAL_DAC_ConfigChannel(&hdac1, &sConfig, DAC_CHANNEL_1) != HAL_OK)
  {
    Error_Handler();
  }

}

static void MX_I2C1_Init(void)
{

  hi2c1.Instance = I2C1;
  hi2c1.Init.Timing = 0x0020081F;
  hi2c1.Init.OwnAddress1 = 0;
  hi2c1.Init.AddressingMode = I2C_ADDRESSINGMODE_7BIT;
  hi2c1.Init.DualAddressMode = I2C_DUALADDRESS_DISABLE;
  hi2c1.Init.OwnAddress2 = 0;
  hi2c1.Init.OwnAddress2Masks = I2C_OA2_NOMASK;
  hi2c1.Init.GeneralCallMode = I2C_GENERALCALL_DISABLE;
  hi2c1.Init.NoStretchMode = I2C_NOSTRETCH_DISABLE;
  if (HAL_I2C_Init(&hi2c1) != HAL_OK)
  {
    Error_Handler();
  }

  /** Configure Analogue filter
  */
  if (HAL_I2CEx_ConfigAnalogFilter(&hi2c1, I2C_ANALOGFILTER_ENABLE) != HAL_OK)
  {
    Error_Handler();
  }

  /** Configure Digital filter
  */
  if (HAL_I2CEx_ConfigDigitalFilter(&hi2c1, 0) != HAL_OK)
  {
    Error_Handler();
  }

  /** I2C Enable Fast Mode Plus
  */
  HAL_I2CEx_EnableFastModePlus(I2C_FASTMODEPLUS_I2C1);

}

static void MX_RTC_Init(void)
{

  RTC_TimeTypeDef sTime = {0};
  RTC_DateTypeDef sDate = {0};

  /** Initialize RTC Only
  */
  hrtc.Instance = RTC;
  hrtc.Init.HourFormat = RTC_HOURFORMAT_24;
  hrtc.Init.AsynchPrediv = 100-1;
  hrtc.Init.SynchPrediv = 10000-1;
  hrtc.Init.OutPut = RTC_OUTPUT_DISABLE;
  hrtc.Init.OutPutPolarity = RTC_OUTPUT_POLARITY_HIGH;
  hrtc.Init.OutPutType = RTC_OUTPUT_TYPE_OPENDRAIN;
  hrtc.Init.OutPutRemap = RTC_OUTPUT_REMAP_NONE;
  if (HAL_RTC_Init(&hrtc) != HAL_OK)
  {
    Error_Handler();
  }

  /** Initialize RTC and set the Time and Date
  */
  sTime.Hours = 0x0;
  sTime.Minutes = 0x0;
  sTime.Seconds = 0x0;
  sTime.DayLightSaving = RTC_DAYLIGHTSAVING_NONE;
  sTime.StoreOperation = RTC_STOREOPERATION_RESET;
  if (HAL_RTC_SetTime(&hrtc, &sTime, RTC_FORMAT_BCD) != HAL_OK)
  {
    Error_Handler();
  }
  sDate.WeekDay = RTC_WEEKDAY_MONDAY;
  sDate.Month = RTC_MONTH_JANUARY;
  sDate.Date = 0x1;
  sDate.Year = 0x0;

  if (HAL_RTC_SetDate(&hrtc, &sDate, RTC_FORMAT_BCD) != HAL_OK)
  {
    Error_Handler();
  }

}

static void MX_SPI1_Init(void)
{

  /* SPI1 parameter configuration*/
  hspi1.Instance = SPI1;
  hspi1.Init.Mode = SPI_MODE_MASTER;
  hspi1.Init.Direction = SPI_DIRECTION_2LINES_RXONLY;
  hspi1.Init.DataSize = SPI_DATASIZE_16BIT;
  hspi1.Init.CLKPolarity = SPI_POLARITY_LOW;
  hspi1.Init.CLKPhase = SPI_PHASE_1EDGE;
  hspi1.Init.NSS = SPI_NSS_SOFT;
  hspi1.Init.BaudRatePrescaler = SPI_BAUDRATEPRESCALER_256;
  hspi1.Init.FirstBit = SPI_FIRSTBIT_MSB;
  hspi1.Init.TIMode = SPI_TIMODE_DISABLE;
  hspi1.Init.CRCCalculation = SPI_CRCCALCULATION_DISABLE;
  hspi1.Init.CRCPolynomial = 0x0;
  hspi1.Init.NSSPMode = SPI_NSS_PULSE_ENABLE;
  hspi1.Init.NSSPolarity = SPI_NSS_POLARITY_LOW;
  hspi1.Init.FifoThreshold = SPI_FIFO_THRESHOLD_01DATA;
  hspi1.Init.TxCRCInitializationPattern = SPI_CRC_INITIALIZATION_ALL_ZERO_PATTERN;
  hspi1.Init.RxCRCInitializationPattern = SPI_CRC_INITIALIZATION_ALL_ZERO_PATTERN;
  hspi1.Init.MasterSSIdleness = SPI_MASTER_SS_IDLENESS_00CYCLE;
  hspi1.Init.MasterInterDataIdleness = SPI_MASTER_INTERDATA_IDLENESS_00CYCLE;
  hspi1.Init.MasterReceiverAutoSusp = SPI_MASTER_RX_AUTOSUSP_DISABLE;
  hspi1.Init.MasterKeepIOState = SPI_MASTER_KEEP_IO_STATE_DISABLE;
  hspi1.Init.IOSwap = SPI_IO_SWAP_DISABLE;
  if (HAL_SPI_Init(&hspi1) != HAL_OK)
  {
    Error_Handler();
  }

}

static void MX_SPI2_Init(void)
{

  /* SPI2 parameter configuration*/
  hspi2.Instance = SPI2;
  hspi2.Init.Mode = SPI_MODE_MASTER;
  hspi2.Init.Direction = SPI_DIRECTION_2LINES_RXONLY;
  hspi2.Init.DataSize = SPI_DATASIZE_16BIT;
  hspi2.Init.CLKPolarity = SPI_POLARITY_LOW;
  hspi2.Init.CLKPhase = SPI_PHASE_1EDGE;
  hspi2.Init.NSS = SPI_NSS_SOFT;
  hspi2.Init.BaudRatePrescaler = SPI_BAUDRATEPRESCALER_256;
  hspi2.Init.FirstBit = SPI_FIRSTBIT_MSB;
  hspi2.Init.TIMode = SPI_TIMODE_DISABLE;
  hspi2.Init.CRCCalculation = SPI_CRCCALCULATION_DISABLE;
  hspi2.Init.CRCPolynomial = 0x0;
  hspi2.Init.NSSPMode = SPI_NSS_PULSE_ENABLE;
  hspi2.Init.NSSPolarity = SPI_NSS_POLARITY_LOW;
  hspi2.Init.FifoThreshold = SPI_FIFO_THRESHOLD_01DATA;
  hspi2.Init.TxCRCInitializationPattern = SPI_CRC_INITIALIZATION_ALL_ZERO_PATTERN;
  hspi2.Init.RxCRCInitializationPattern = SPI_CRC_INITIALIZATION_ALL_ZERO_PATTERN;
  hspi2.Init.MasterSSIdleness = SPI_MASTER_SS_IDLENESS_00CYCLE;
  hspi2.Init.MasterInterDataIdleness = SPI_MASTER_INTERDATA_IDLENESS_00CYCLE;
  hspi2.Init.MasterReceiverAutoSusp = SPI_MASTER_RX_AUTOSUSP_DISABLE;
  hspi2.Init.MasterKeepIOState = SPI_MASTER_KEEP_IO_STATE_DISABLE;
  hspi2.Init.IOSwap = SPI_IO_SWAP_DISABLE;
  if (HAL_SPI_Init(&hspi2) != HAL_OK)
  {
    Error_Handler();
  }

}

static void MX_TIM1_Init(void)
{

  TIM_ClockConfigTypeDef sClockSourceConfig = {0};
  TIM_MasterConfigTypeDef sMasterConfig = {0};
  TIM_OC_InitTypeDef sConfigOC = {0};
  TIM_BreakDeadTimeConfigTypeDef sBreakDeadTimeConfig = {0};

  htim1.Instance = TIM1;
  htim1.Init.Prescaler = 50-1;
  htim1.Init.CounterMode = TIM_COUNTERMODE_UP;
  htim1.Init.Period = 62500-1;
  htim1.Init.ClockDivision = TIM_CLOCKDIVISION_DIV1;
  htim1.Init.RepetitionCounter = 0;
  htim1.Init.AutoReloadPreload = TIM_AUTORELOAD_PRELOAD_DISABLE;
  if (HAL_TIM_Base_Init(&htim1) != HAL_OK)
  {
    Error_Handler();
  }
  sClockSourceConfig.ClockSource = TIM_CLOCKSOURCE_INTERNAL;
  if (HAL_TIM_ConfigClockSource(&htim1, &sClockSourceConfig) != HAL_OK)
  {
    Error_Handler();
  }
  if (HAL_TIM_PWM_Init(&htim1) != HAL_OK)
  {
    Error_Handler();
  }
  sMasterConfig.MasterOutputTrigger = TIM_TRGO_RESET;
  sMasterConfig.MasterOutputTrigger2 = TIM_TRGO2_RESET;
  sMasterConfig.MasterSlaveMode = TIM_MASTERSLAVEMODE_DISABLE;
  if (HAL_TIMEx_MasterConfigSynchronization(&htim1, &sMasterConfig) != HAL_OK)
  {
    Error_Handler();
  }
  sConfigOC.OCMode = TIM_OCMODE_PWM1;
  sConfigOC.Pulse = 480-1;
  sConfigOC.OCPolarity = TIM_OCPOLARITY_HIGH;
  sConfigOC.OCNPolarity = TIM_OCNPOLARITY_HIGH;
  sConfigOC.OCFastMode = TIM_OCFAST_DISABLE;
  sConfigOC.OCIdleState = TIM_OCIDLESTATE_RESET;
  sConfigOC.OCNIdleState = TIM_OCNIDLESTATE_RESET;
  if (HAL_TIM_PWM_ConfigChannel(&htim1, &sConfigOC, TIM_CHANNEL_1) != HAL_OK)
  {
    Error_Handler();
  }
  sBreakDeadTimeConfig.OffStateRunMode = TIM_OSSR_DISABLE;
  sBreakDeadTimeConfig.OffStateIDLEMode = TIM_OSSI_DISABLE;
  sBreakDeadTimeConfig.LockLevel = TIM_LOCKLEVEL_OFF;
  sBreakDeadTimeConfig.DeadTime = 0;
  sBreakDeadTimeConfig.BreakState = TIM_BREAK_DISABLE;
  sBreakDeadTimeConfig.BreakPolarity = TIM_BREAKPOLARITY_HIGH;
  sBreakDeadTimeConfig.BreakFilter = 0;
  sBreakDeadTimeConfig.Break2State = TIM_BREAK2_DISABLE;
  sBreakDeadTimeConfig.Break2Polarity = TIM_BREAK2POLARITY_HIGH;
  sBreakDeadTimeConfig.Break2Filter = 0;
  sBreakDeadTimeConfig.AutomaticOutput = TIM_AUTOMATICOUTPUT_DISABLE;
  if (HAL_TIMEx_ConfigBreakDeadTime(&htim1, &sBreakDeadTimeConfig) != HAL_OK)
  {
    Error_Handler();
  }
  HAL_TIM_MspPostInit(&htim1);

}

static void MX_TIM2_Init(void)
{

  TIM_ClockConfigTypeDef sClockSourceConfig = {0};
  TIM_MasterConfigTypeDef sMasterConfig = {0};
  TIM_OC_InitTypeDef sConfigOC = {0};

  htim2.Instance = TIM2;
  htim2.Init.Prescaler = 50-1;
  htim2.Init.CounterMode = TIM_COUNTERMODE_UP;
  htim2.Init.Period = 3125-1;
  htim2.Init.ClockDivision = TIM_CLOCKDIVISION_DIV1;
  htim2.Init.AutoReloadPreload = TIM_AUTORELOAD_PRELOAD_ENABLE;
  if (HAL_TIM_Base_Init(&htim2) != HAL_OK)
  {
    Error_Handler();
  }
  sClockSourceConfig.ClockSource = TIM_CLOCKSOURCE_INTERNAL;
  if (HAL_TIM_ConfigClockSource(&htim2, &sClockSourceConfig) != HAL_OK)
  {
    Error_Handler();
  }
  if (HAL_TIM_PWM_Init(&htim2) != HAL_OK)
  {
    Error_Handler();
  }
  sMasterConfig.MasterOutputTrigger = TIM_TRGO_UPDATE;
  sMasterConfig.MasterSlaveMode = TIM_MASTERSLAVEMODE_DISABLE;
  if (HAL_TIMEx_MasterConfigSynchronization(&htim2, &sMasterConfig) != HAL_OK)
  {
    Error_Handler();
  }
  sConfigOC.OCMode = TIM_OCMODE_PWM1;
  sConfigOC.Pulse = 0;
  sConfigOC.OCPolarity = TIM_OCPOLARITY_HIGH;
  sConfigOC.OCFastMode = TIM_OCFAST_DISABLE;
  if (HAL_TIM_PWM_ConfigChannel(&htim2, &sConfigOC, TIM_CHANNEL_4) != HAL_OK)
  {
    Error_Handler();
  }
  HAL_TIM_MspPostInit(&htim2);

}

static void MX_TIM3_Init(void)
{

  TIM_ClockConfigTypeDef sClockSourceConfig = {0};
  TIM_MasterConfigTypeDef sMasterConfig = {0};

  htim3.Instance = TIM3;
  htim3.Init.Prescaler = 100-1;
  htim3.Init.CounterMode = TIM_COUNTERMODE_UP;
  htim3.Init.Period = 50000-1;
  htim3.Init.ClockDivision = TIM_CLOCKDIVISION_DIV1;
  htim3.Init.AutoReloadPreload = TIM_AUTORELOAD_PRELOAD_DISABLE;
  if (HAL_TIM_Base_Init(&htim3) != HAL_OK)
  {
    Error_Handler();
  }
  sClockSourceConfig.ClockSource = TIM_CLOCKSOURCE_INTERNAL;
  if (HAL_TIM_ConfigClockSource(&htim3, &sClockSourceConfig) != HAL_OK)
  {
    Error_Handler();
  }
  sMasterConfig.MasterOutputTrigger = TIM_TRGO_RESET;
  sMasterConfig.MasterSlaveMode = TIM_MASTERSLAVEMODE_DISABLE;
  if (HAL_TIMEx_MasterConfigSynchronization(&htim3, &sMasterConfig) != HAL_OK)
  {
    Error_Handler();
  }

}

static void MX_USART1_UART_Init(void)
{

  huart1.Instance = USART1;
  huart1.Init.BaudRate = 460800;
  huart1.Init.WordLength = UART_WORDLENGTH_8B;
  huart1.Init.StopBits = UART_STOPBITS_1;
  huart1.Init.Parity = UART_PARITY_NONE;
  huart1.Init.Mode = UART_MODE_TX_RX;
  huart1.Init.HwFlowCtl = UART_HWCONTROL_NONE;
  huart1.Init.OverSampling = UART_OVERSAMPLING_16;
  huart1.Init.OneBitSampling = UART_ONE_BIT_SAMPLE_DISABLE;
  huart1.Init.ClockPrescaler = UART_PRESCALER_DIV1;
  huart1.AdvancedInit.AdvFeatureInit = UART_ADVFEATURE_NO_INIT;
  if (HAL_UART_Init(&huart1) != HAL_OK)
  {
    Error_Handler();
  }
  if (HAL_UARTEx_SetTxFifoThreshold(&huart1, UART_TXFIFO_THRESHOLD_1_8) != HAL_OK)
  {
    Error_Handler();
  }
  if (HAL_UARTEx_SetRxFifoThreshold(&huart1, UART_RXFIFO_THRESHOLD_1_8) != HAL_OK)
  {
    Error_Handler();
  }
  if (HAL_UARTEx_DisableFifoMode(&huart1) != HAL_OK)
  {
    Error_Handler();
  }
  /* USER CODE BEGIN USART1_Init 2 */
	/* Set the RXFIFO threshold */
	HAL_UARTEx_SetRxFifoThreshold(&huart1, UART_RXFIFO_THRESHOLD_1_4);

	/* Enable the FIFO mode */
	HAL_UARTEx_EnableFifoMode(&huart1);

	/* Enable MCU wakeup by UART */
	HAL_UARTEx_EnableStopMode(&huart1);

	/* Enable the UART RX FIFO threshold interrupt */
	__HAL_UART_ENABLE_IT(&huart1, UART_IT_RXFT);

	/* Enable the UART wakeup from stop mode interrupt */
	__HAL_UART_ENABLE_IT(&huart1, UART_IT_WUF);

	/* Put UART peripheral in reception process */
//	HAL_UART_Receive_IT(&huart1, UART_RX_BUFFER, 1);
  /* USER CODE END USART1_Init 2 */

}

static void MX_DMA_Init(void)
{

  /* DMA controller clock enable */
  __HAL_RCC_DMA1_CLK_ENABLE();

  /* DMA interrupt init */
  /* DMA1_Stream0_IRQn interrupt configuration */
  HAL_NVIC_SetPriority(DMA1_Stream0_IRQn, 5, 0);
  HAL_NVIC_EnableIRQ(DMA1_Stream0_IRQn);
  /* DMA1_Stream1_IRQn interrupt configuration */
  HAL_NVIC_SetPriority(DMA1_Stream1_IRQn, 5, 0);
  HAL_NVIC_EnableIRQ(DMA1_Stream1_IRQn);
  /* DMA1_Stream2_IRQn interrupt configuration */
  HAL_NVIC_SetPriority(DMA1_Stream2_IRQn, 5, 0);
  HAL_NVIC_EnableIRQ(DMA1_Stream2_IRQn);
  /* DMA1_Stream5_IRQn interrupt configuration */
  HAL_NVIC_SetPriority(DMA1_Stream5_IRQn, 5, 0);
  HAL_NVIC_EnableIRQ(DMA1_Stream5_IRQn);

}

static void MX_GPIO_Init(void)
{
  GPIO_InitTypeDef GPIO_InitStruct = {0};

  /* GPIO Ports Clock Enable */
  __HAL_RCC_GPIOC_CLK_ENABLE();
  __HAL_RCC_GPIOH_CLK_ENABLE();
  __HAL_RCC_GPIOA_CLK_ENABLE();
  __HAL_RCC_GPIOB_CLK_ENABLE();

  /*Configure GPIO pin Output Level */
  HAL_GPIO_WritePin(GPIOC, GPIO_PIN_13|GPIO_PIN_6|GPIO_PIN_7|GPIO_PIN_8
                          |GPIO_PIN_9|GPIO_PIN_10, GPIO_PIN_RESET);

  /*Configure GPIO pin Output Level */
  HAL_GPIO_WritePin(GPIOB, GPIO_PIN_2|GPIO_PIN_5|GPIO_PIN_6, GPIO_PIN_RESET);

  /*Configure GPIO pins : PC13 PC6 PC7 PC8
                           PC9 PC10 */
  GPIO_InitStruct.Pin = GPIO_PIN_13|GPIO_PIN_6|GPIO_PIN_7|GPIO_PIN_8
                          |GPIO_PIN_9|GPIO_PIN_10;
  GPIO_InitStruct.Mode = GPIO_MODE_OUTPUT_PP;
  GPIO_InitStruct.Pull = GPIO_PULLDOWN;
  GPIO_InitStruct.Speed = GPIO_SPEED_FREQ_LOW;
  HAL_GPIO_Init(GPIOC, &GPIO_InitStruct);

  /*Configure GPIO pins : PB2 PB5 PB6 */
  GPIO_InitStruct.Pin = GPIO_PIN_2|GPIO_PIN_5|GPIO_PIN_6;
  GPIO_InitStruct.Mode = GPIO_MODE_OUTPUT_PP;
  GPIO_InitStruct.Pull = GPIO_PULLDOWN;
  GPIO_InitStruct.Speed = GPIO_SPEED_FREQ_LOW;
  HAL_GPIO_Init(GPIOB, &GPIO_InitStruct);

}

/* USER CODE BEGIN 4 */
// *********************************************************************************************************** RAW DATA RETRIEVAL FUNCTIONS
/**
 * @brief Polls an I2C temperature sensor.
 *
 * This function transmits a read request to the specified I2C temperature sensor
 * and reads the temperature value.
 *
 * @param TEMP_ADDR The I2C address of the temperature sensor.
 * @return The temperature reading from the sensor, or an error code.
 */
int16_t poll_i2c_sensor(const uint8_t TEMP_ADDR) {
	int16_t output;
	uint8_t buf[2];
	HAL_StatusTypeDef ret;
	buf[0] = REG_TEMP;
	ret = HAL_I2C_Master_Transmit(&hi2c1, TEMP_ADDR, buf, 1, 1000);
	if (ret != HAL_OK) {
		printf("I2C TX Error\n");
	} else {
		/* Read 2 bytes from the temperature register */
		ret = HAL_I2C_Master_Receive(&hi2c1, TEMP_ADDR, buf, 2, 1000);
		if (ret != HAL_OK) {
			printf("I2C RX Error\n");
		} else {
			output = (int16_t) (buf[0] << 8);
			output = (output | buf[1]) >> 3;
		}
	}
	return output;
}

/**
 * @brief Receives data from an SPI device.
 *
 * This function receives data from the specified SPI device and stores the result
 * in the provided buffer.
 *
 * @param spi_handle The handle to the SPI device.
 * @param buffer The buffer to store the received data.
 */
void receive_pmt_spi(uint8_t *buffer) {
	uint8_t spi_raw_data[2];
	uint8_t spi_MSB;
	uint8_t spi_LSB;

	HAL_SPI_Receive(&hspi1, (uint8_t*) spi_raw_data, 1, 1);

	spi_LSB = ((spi_raw_data[0] & 0xFF00) >> 8);
	spi_MSB = (spi_raw_data[1] & 0xFF);

	hspi1.Instance->CR1 |= 1 << 10;

	buffer[0] = spi_MSB;
	buffer[1] = spi_LSB;
}

/**
 * @brief Receives data from an SPI device.
 *
 * This function receives data from the specified SPI device and stores the result
 * in the provided buffer.
 *
 * @param spi_handle The handle to the SPI device.
 * @param buffer The buffer to store the received data.
 */
void receive_erpa_spi(uint8_t *buffer) {
	uint8_t spi_raw_data[2];
	uint8_t spi_MSB;
	uint8_t spi_LSB;

	HAL_SPI_Receive(&hspi2, (uint8_t*) spi_raw_data, 1, 100);

	spi_LSB = ((spi_raw_data[0] & 0xFF00) >> 8);
	spi_MSB = (spi_raw_data[1] & 0xFF);

	hspi2.Instance->CR1 |= 1 << 10;

	buffer[0] = spi_MSB;
	buffer[1] = spi_LSB;
}

/**
 * @brief Receives ERPA ADC data and stores it in the provided buffer.
 *
 * @param buffer Pointer to an array where ADC data will be stored.
 *
 * This function reads the raw data from the ERPA ADC and writes it to the
 * first element of the provided buffer.
 */
void receive_erpa_adc(uint16_t *buffer) {
	uint16_t PC4 = ADC1_raw_data[1];

	buffer[0] = PC4;
}

/**
 * @brief Receives housekeeping I2C sensor data.
 *
 * This function polls multiple I2C sensors and stores the results in the provided buffer.
 *
 * @param buffer The buffer to store the received I2C sensor data.
 */
void receive_hk_i2c(int16_t *buffer) {
	int16_t output1 = poll_i2c_sensor(ADT7410_1);
	int16_t output2 = poll_i2c_sensor(ADT7410_2);
	int16_t output3 = poll_i2c_sensor(ADT7410_3);
	int16_t output4 = poll_i2c_sensor(ADT7410_4);

	buffer[0] = output1;
	buffer[1] = output2;
	buffer[2] = output3;
	buffer[3] = output4;
}

/**
 * @brief Receives housekeeping ADC1 data and stores it in the provided buffer.
 *
 * @param buffer Pointer to an array where ADC data will be stored.
 *
 * This function reads the raw housekeeping ADC1 data and writes it to the
 * corresponding elements of the provided buffer.
 */
void receive_hk_adc1(uint16_t *buffer) {
	uint16_t PA1 = ADC1_raw_data[10];
	uint16_t PA2 = ADC1_raw_data[8];
	uint16_t PC0 = ADC1_raw_data[6];
	uint16_t PA3 = ADC1_raw_data[9];
	uint16_t PB1 = ADC1_raw_data[2];
	uint16_t PA7 = ADC1_raw_data[3];
	uint16_t PC1 = ADC1_raw_data[7];
	uint16_t PC5 = ADC1_raw_data[4];
	uint16_t PA6 = ADC1_raw_data[0];
	uint16_t PB0 = ADC1_raw_data[5];

	buffer[0] = PA1;
	buffer[1] = PA2;
	buffer[2] = PC0;
	buffer[3] = PA3;
	buffer[4] = PB1;
	buffer[5] = PA7;
	buffer[6] = PC1;
	buffer[7] = PC5;
	buffer[8] = PA6;
	buffer[9] = PB0;
}

/**
 * @brief Receives housekeeping ADC3 sensor data.
 *
 * This function retrieves specific ADC3 sensor data and stores the results in the provided buffer.
 *
 * @param buffer The buffer to store the received ADC3 sensor data.
 */
void receive_hk_adc3(uint16_t *buffer) {
	uint16_t vrefint = ADC3_raw_data[0];
	uint16_t vsense = ADC3_raw_data[1];
	uint16_t PC2 = ADC3_raw_data[2];
	uint16_t PC3 = ADC3_raw_data[3];

	buffer[0] = vrefint;
	buffer[1] = vsense;
	buffer[2] = PC2;
	buffer[3] = PC3;
}

// *********************************************************************************************************** HELPER FUNCTIONS

/**
 * @brief Gets the current step based on the DAC value.
 *
 * @return uint8_t The current step number or -1 if the DAC value is invalid.
 *
 * This function reads the current value from the DAC and returns the corresponding
 * step based on predefined DAC values.
 */
uint8_t get_current_step() {
	int dac_value;

	dac_value = DAC1->DHR12R1;

	switch (dac_value) {
	case 0:
		return 0;
	case 620:
		return 1;
	case 1241:
		return 2;
	case 1861:
		return 3;
	case 2482:
		return 4;
	case 3103:
		return 5;
	case 3723:
		return 6;
	case 4095:
		return 7;
	default:
		return -1;
	}
}

/**
 * @brief Enters STOP mode and configures the system upon wakeup.
 *
 * This function sends an acknowledgment message, suspends all tasks, and
 * enters STOP mode. Upon waking up, it resumes all tasks and reconfigures
 * the system clock.
 */
void enter_stop() {

	//flush_message_queue();
	send_ACK();

	vTaskSuspendAll();
	HAL_PWR_EnterSTOPMode(PWR_LOWPOWERREGULATOR_ON, PWR_STOPENTRY_WFI);

	// When MCU is triggered to wake up, it resumes right here.
	// That's why it looks like we enter stop mode and then instantly
	// configure the clock and resume tasks, but in reality the MCU
	// just stops right here.

	SystemClock_Config();
	xTaskResumeAll();
}

HAL_StatusTypeDef RTC_SetTime(RTC_HandleTypeDef *hrtc, RTC_TimeTypeDef *sTime,
		uint32_t Format) {
	uint32_t tmpreg;
	HAL_StatusTypeDef status;

	/* Process Locked */
	__HAL_LOCK(hrtc);

	hrtc->State = HAL_RTC_STATE_BUSY;

	/* Disable the write protection for RTC registers */
	__HAL_RTC_WRITEPROTECTION_DISABLE(hrtc);
	/* Enter Initialization mode */
	status = RTC_EnterInitMode(hrtc);
	if (status == HAL_OK) {

		sTime->TimeFormat = 0x00U;
		assert_param(IS_RTC_HOUR24(sTime->Hours));

		assert_param(IS_RTC_MINUTES(sTime->Minutes));
		assert_param(IS_RTC_SECONDS(sTime->Seconds));

		tmpreg = (uint32_t) (((uint32_t) RTC_ByteToBcd2(sTime->Hours)
				<< RTC_TR_HU_Pos)
				| ((uint32_t) RTC_ByteToBcd2(sTime->Minutes) << RTC_TR_MNU_Pos)
				| ((uint32_t) RTC_ByteToBcd2(sTime->Seconds) << RTC_TR_SU_Pos)
				| (((uint32_t) sTime->TimeFormat) << RTC_TR_PM_Pos));

		/* Set the RTC_TR register */
		hrtc->Instance->TR = (uint32_t) (tmpreg & RTC_TR_RESERVED_MASK);

		/* Exit Initialization mode */
		status = RTC_ExitInitMode(hrtc);
	}

	/* Enable the write protection for RTC registers */
	__HAL_RTC_WRITEPROTECTION_ENABLE(hrtc);

	if (status == HAL_OK) {
		hrtc->State = HAL_RTC_STATE_READY;
	}

	/* Process Unlocked */
	__HAL_UNLOCK(hrtc);
	return status;

}
/**
 * @brief Calibrates the RTC with the provided date and time values.
 *
 * @param buffer Pointer to an array containing date and time values.
 *
 * This function extracts date and time information from the provided buffer
 * and sets the RTC accordingly. It handles years, months, days, hours, minutes,
 * seconds, and milliseconds.
 */
void calibrateRTC(uint8_t *buffer) {
	//    [0]     [1]     [2]     [3]     [4]     [5]     [6]     [7]     [8]
	//    0xFF    Year   Month    Day     Hour   Minute  Second  ms MSB  ms LSB

	RTC_DateTypeDef date_struct;
	RTC_TimeTypeDef time_struct;
	uint8_t year = buffer[1];
	uint8_t month = buffer[2];
	uint8_t day = buffer[3];
	uint8_t hour = buffer[4];
	uint8_t minute = buffer[5];
	uint8_t second = buffer[6];
	uint16_t milliseconds = (buffer[7] << 8) | buffer[8];

	date_struct.Year = year;
	date_struct.Month = month;
	date_struct.Date = day;

	time_struct.Hours = hour;
	time_struct.Minutes = minute;
	time_struct.Seconds = second;
	time_struct.SubSeconds = milliseconds;

	HAL_StatusTypeDef status;

	status = HAL_RTC_SetDate(&hrtc, &date_struct, RTC_FORMAT_BIN);
	if (status != HAL_OK) {
		Error_Handler();
	}
	RTC_SetTime(&hrtc, &time_struct, RTC_FORMAT_BIN);

//	status = HAL_RTC_SetTime(&hrtc, &time_struct, RTC_FORMAT_BIN);
//	if (status != HAL_OK) {
//		Error_Handler();
//	}
}

/**
 * @brief Synchronizes the system's RTC with the OBC/GUI timestamp.
 *
 * This function performs the following steps to synchronize the RTC:
 * 1. Sends an acknowledgment to indicate the system is awake.
 * 2. Waits to receive an RTC-generated timestamp from the OBC/GUI.
 * 3. Calibrates the RTC with the received timestamp.
 * 4. Sends an acknowledgment to indicate the RTC calibration is complete.
 */
void sync() {
	send_ACK();

	uint8_t key;

	// Wait for 0xFF to be received
	HAL_UART_AbortReceive(&huart1);
	do {
		HAL_UART_Receive(&huart1, UART_RX_BUFFER, 9, 100);
		key = UART_RX_BUFFER[0];
	} while (key != 0xFF);

	calibrateRTC(UART_RX_BUFFER);
	HAL_UART_Receive_IT(&huart1, UART_RX_BUFFER, 1);

	send_ACK();
}

/**
 * @brief Sends an acknowledgment byte via UART.
 *
 * This function sends a single acknowledgment byte (0xFF) using the UART
 * interface to indicate a successful operation or state transition.
 */
void send_ACK() {
	static uint8_t tx_buffer[1];

	tx_buffer[0] = ACK;
	HAL_UART_Transmit(&huart1, tx_buffer, 1, 100);
}

/**
 * @brief Sends a negative acknowledgment byte via UART.
 *
 * This function sends a single negative acknowledgment byte (0x00) using the UART
 * interface to indicate a failed operation or state transition.
 */
void send_NACK() {
	static uint8_t tx_buffer[1];

	tx_buffer[0] = NACK;
	HAL_UART_Transmit(&huart1, tx_buffer, 1, 100);

}

/**
 * @brief Flushes the message queue and sends accumulated messages via UART.
 *
 * This function retrieves messages from the message queue and accumulates
 * them in a buffer. When the buffer is full or the queue is empty, it sends
 * the buffer contents via UART using DMA. It waits for the transmission
 * to complete before returning.
 */
void flush_message_queue() {
	static uint8_t tx_buffer[UART_TX_BUFFER_SIZE];

	uint32_t total_size = 0;
	osStatus_t status;
	do {
		status = osMessageQueueGet(mid_MsgQueue, &msg, NULL, osWaitForever);
		if (status == osOK) {
			if ((total_size + msg.size) < UART_TX_BUFFER_SIZE) {
				memcpy(&tx_buffer[total_size], msg.array, msg.size);
				free(msg.array);
				total_size += msg.size;
				if (total_size >= (UART_TX_BUFFER_SIZE - HK_DATA_SIZE)) {
					break;
				}
			}
		} else {
			break;
		}
	} while (status == osOK);

	if (total_size > 0) {
		HAL_UART_Transmit_DMA(&huart1, tx_buffer, total_size);

		// Wait for transmission to complete
		while (tx_flag == 0) {
		}

		tx_flag = 0;

	}
}

/**
 * @brief Checks if a value is within a specified range.
 *
 * @param raw The value to check.
 * @param min The minimum value of the range (inclusive).
 * @param max The maximum value of the range (inclusive).
 *
 * @return int Returns 1 if the value is within the range, otherwise 0.
 */
int in_range(uint16_t raw, int min, int max) {
	if (raw <= max && raw >= min) {
		return 1;
	}
	return 0;
}

/**
 * @brief Handles error reporting by creating and sending an error packet.
 *
 * @param tag An identifier for the type of error.
 *
 * This function samples the housekeeping data, creates an error packet with
 * the provided error tag, and places it in the message queue. It also includes
 * synchronization bytes in the packet. The function currently includes a TODO
 * for adding shutdown procedures.
 */
void error_protocol(VOLTAGE_RAIL_NAME failed_rail) {
	vTaskSuspend(HK_taskHandle);
	vTaskSuspend(ERPA_taskHandle);
	vTaskSuspend(PMT_taskHandle);

	sample_hk();
	packet_t error_packet;
	uint8_t *buffer = (uint8_t*) malloc(
	ERROR_PACKET_DATA_SIZE * sizeof(uint8_t));

	buffer[0] = ERROR_SYNC;
	buffer[1] = ERROR_SYNC;
	buffer[2] = failed_rail;

	error_packet = create_packet(buffer, ERROR_PACKET_DATA_SIZE);
	osMessageQueuePut(mid_MsgQueue, &error_packet, 0U, 0U);

	free(buffer);
	//vTaskSuspendAll();
	//TODO: Shutdown
}

/**
 * @brief UART transmit complete callback.
 * @param huart: UART handle.
 */
void HAL_UART_TxCpltCallback(UART_HandleTypeDef *huart) {
	tx_flag = 1;
}

/**
 * @brief Creates a packet with given data and size.
 * @param data: Pointer to data to be copied into the packet.
 * @param size: Size of the data.
 * @return Created packet.
 */
packet_t create_packet(const uint8_t *data, uint16_t size) {
	packet_t packet;
	packet.array = (uint8_t*) malloc(size * sizeof(uint8_t));
	if (packet.array == NULL) {
		// Packet array is null somehow, should probably do something about this edge case
	}
	memcpy(packet.array, data, size);
	packet.size = size;
	return packet;
}

/**
 * @brief Performs system initialization and configuration.
 *
 * This function starts a timer channel, calibrates and starts ADCs with DMA,
 * and initializes UART reception. It sets up various hardware components
 * and checks for errors during the configuration process.
 */
void system_setup() {

	rail_monitor[RAIL_vsense].name = RAIL_vsense;
	rail_monitor[RAIL_vsense].error_count = 0;
	rail_monitor[RAIL_vsense].is_enabled = 1;
	rail_monitor[RAIL_vsense].data = 0;
	rail_monitor[RAIL_vsense].max_voltage = 10000; // TODO: Get actual range from Sanj
	rail_monitor[RAIL_vsense].min_voltage = 0;

	rail_monitor[RAIL_vrefint].name = RAIL_vrefint;
	rail_monitor[RAIL_vrefint].error_count = 0;
	rail_monitor[RAIL_vrefint].is_enabled = 1;
	rail_monitor[RAIL_vrefint].data = 0;
	rail_monitor[RAIL_vrefint].max_voltage = 10000; // TODO: Get actual range from Sanj
	rail_monitor[RAIL_vrefint].min_voltage = 0;

	rail_monitor[RAIL_TEMP1].name = RAIL_TEMP1;
	rail_monitor[RAIL_TEMP1].error_count = 0;
	rail_monitor[RAIL_TEMP1].is_enabled = 1;
	rail_monitor[RAIL_TEMP1].data = 0;
	rail_monitor[RAIL_TEMP1].max_voltage = 10000; // TODO: Get actual range from Sanj
	rail_monitor[RAIL_TEMP1].min_voltage = 0;

	rail_monitor[RAIL_TEMP2].name = RAIL_TEMP2;
	rail_monitor[RAIL_TEMP2].error_count = 0;
	rail_monitor[RAIL_TEMP2].is_enabled = 1;
	rail_monitor[RAIL_TEMP2].data = 0;
	rail_monitor[RAIL_TEMP2].max_voltage = 10000; // TODO: Get actual range from Sanj
	rail_monitor[RAIL_TEMP2].min_voltage = 0;

	rail_monitor[RAIL_TEMP3].name = RAIL_TEMP3;
	rail_monitor[RAIL_TEMP3].error_count = 0;
	rail_monitor[RAIL_TEMP3].is_enabled = 1;
	rail_monitor[RAIL_TEMP3].data = 0;
	rail_monitor[RAIL_TEMP3].max_voltage = 10000; // TODO: Get actual range from Sanj
	rail_monitor[RAIL_TEMP3].min_voltage = 0;

	rail_monitor[RAIL_TEMP4].name = RAIL_TEMP4;
	rail_monitor[RAIL_TEMP4].error_count = 0;
	rail_monitor[RAIL_TEMP4].is_enabled = 1;
	rail_monitor[RAIL_TEMP4].data = 0;
	rail_monitor[RAIL_TEMP4].max_voltage = 10000; // TODO: Get actual range from Sanj
	rail_monitor[RAIL_TEMP4].min_voltage = 0;

	rail_monitor[RAIL_busvmon].name = RAIL_busvmon;
	rail_monitor[RAIL_busvmon].error_count = 0;
	rail_monitor[RAIL_busvmon].is_enabled = 1;
	rail_monitor[RAIL_busvmon].data = 0;
	rail_monitor[RAIL_busvmon].max_voltage = 10000; // TODO: Get actual range from Sanj
	rail_monitor[RAIL_busvmon].min_voltage = 0;

	rail_monitor[RAIL_busimon].name = RAIL_busimon;
	rail_monitor[RAIL_busimon].error_count = 0;
	rail_monitor[RAIL_busimon].is_enabled = 1;
	rail_monitor[RAIL_busimon].data = 0;
	rail_monitor[RAIL_busimon].max_voltage = 10000; // TODO: Get actual range from Sanj
	rail_monitor[RAIL_busimon].min_voltage = 0;

	rail_monitor[RAIL_2v5].name = RAIL_2v5;
	rail_monitor[RAIL_2v5].error_count = 0;
	rail_monitor[RAIL_2v5].is_enabled = 0;
	rail_monitor[RAIL_2v5].data = 0;
	rail_monitor[RAIL_2v5].max_voltage = 3257;
	rail_monitor[RAIL_2v5].min_voltage = 2947;

	rail_monitor[RAIL_3v3].name = RAIL_3v3;
	rail_monitor[RAIL_3v3].error_count = 0;
	rail_monitor[RAIL_3v3].is_enabled = 0;
	rail_monitor[RAIL_3v3].data = 0;
	rail_monitor[RAIL_3v3].max_voltage = 3909;
	//rail_monitor[RAIL_3v3].min_voltage = 3537;
	rail_monitor[RAIL_3v3].min_voltage = 0;

	rail_monitor[RAIL_5v].name = RAIL_5v;
	rail_monitor[RAIL_5v].error_count = 0;
	rail_monitor[RAIL_5v].is_enabled = 0;
	rail_monitor[RAIL_5v].data = 0;
	rail_monitor[RAIL_5v].max_voltage = 3909;
	rail_monitor[RAIL_5v].min_voltage = 3537;

	rail_monitor[RAIL_n3v3].name = RAIL_n3v3;
	rail_monitor[RAIL_n3v3].error_count = 0;
	rail_monitor[RAIL_n3v3].is_enabled = 0;
	rail_monitor[RAIL_n3v3].data = 0;
	rail_monitor[RAIL_n3v3].max_voltage = 4091;
	rail_monitor[RAIL_n3v3].min_voltage = 3702;

	rail_monitor[RAIL_n5v].name = RAIL_n5v;
	rail_monitor[RAIL_n5v].error_count = 0;
	rail_monitor[RAIL_n5v].is_enabled = 0;
	rail_monitor[RAIL_n5v].data = 0;
	rail_monitor[RAIL_n5v].max_voltage = 4000;
	//rail_monitor[RAIL_n5v].min_voltage = 3619;
	rail_monitor[RAIL_n5v].min_voltage = 0;

	rail_monitor[RAIL_15v].name = RAIL_15v;
	rail_monitor[RAIL_15v].error_count = 0;
	rail_monitor[RAIL_15v].is_enabled = 0;
	rail_monitor[RAIL_15v].data = 0;
	rail_monitor[RAIL_15v].max_voltage = 3896;
	rail_monitor[RAIL_15v].min_voltage = 3525;

	rail_monitor[RAIL_5vref].name = RAIL_5vref;
	rail_monitor[RAIL_5vref].error_count = 0;
	rail_monitor[RAIL_5vref].is_enabled = 0;
	rail_monitor[RAIL_5vref].data = 0;
	rail_monitor[RAIL_5vref].max_voltage = 3909;
	rail_monitor[RAIL_5vref].min_voltage = 3537;

	rail_monitor[RAIL_n200v].name = RAIL_n200v;
	rail_monitor[RAIL_n200v].error_count = 0;
	rail_monitor[RAIL_n200v].is_enabled = 0;
	rail_monitor[RAIL_n200v].data = 0;
	rail_monitor[RAIL_n200v].max_voltage = 4196;
	//rail_monitor[RAIL_n200v].min_voltage = 3796;
	rail_monitor[RAIL_n200v].min_voltage = 0;		// TODO: Currently set to 0, kept triggering because it has been reading ~3351

	rail_monitor[RAIL_n800v].name = RAIL_n800v;
	rail_monitor[RAIL_n800v].error_count = 0;
	rail_monitor[RAIL_n800v].is_enabled = 0;
	rail_monitor[RAIL_n800v].data = 0;
	rail_monitor[RAIL_n800v].max_voltage = 3336;
	rail_monitor[RAIL_n800v].min_voltage = 3018;

	rail_monitor[RAIL_TMP1].name = RAIL_TMP1;
	rail_monitor[RAIL_TMP1].error_count = 0;
	rail_monitor[RAIL_TMP1].is_enabled = 1;
	rail_monitor[RAIL_TMP1].data = 0;
	rail_monitor[RAIL_TMP1].max_voltage = 10000; // TODO: Get actual range from Sanj
	rail_monitor[RAIL_TMP1].min_voltage = 0;

	HAL_TIM_OC_Start_IT(&htim3, TIM_CHANNEL_1);

	TIM2->CCR4 = 312;
	if (HAL_ADCEx_Calibration_Start(&hadc1, ADC_CALIB_OFFSET_LINEARITY,
	ADC_SINGLE_ENDED) != HAL_OK) {
		Error_Handler();
	}

	if (HAL_ADC_Start_DMA(&hadc1, (uint32_t*) ADC1_raw_data,
	ADC1_NUM_CHANNELS) != HAL_OK) {
		Error_Handler();
	}

	if (HAL_ADCEx_Calibration_Start(&hadc3, ADC_CALIB_OFFSET_LINEARITY,
	ADC_SINGLE_ENDED) != HAL_OK) {
		Error_Handler();
	}

	if (HAL_ADC_Start_DMA(&hadc3, (uint32_t*) ADC3_raw_data,
	ADC3_NUM_CHANNELS) != HAL_OK) {
		Error_Handler();
	}
	HAL_UART_Receive_IT(&huart1, UART_RX_BUFFER, 1);
}

/**
 * @brief Retrieves the system uptime in milliseconds and stores it in the buffer.
 *
 * @param buffer Pointer to an array where the uptime will be stored as 4 bytes.
 *
 * This function calculates the system uptime based on the `uptime_millis`
 * variable and the current value of the SysTick timer. It handles potential
 * rollovers by checking and correcting the values before storing the uptime
 * in the provided buffer.
 */
void get_uptime(uint8_t *buffer) {
	uint32_t uptime = 0;
	uint32_t ms = uptime_millis;
	uint32_t st = SysTick->VAL;

	// Did uptime_millis rollover while reading SysTick->VAL?
	if (ms != uptime_millis) {
		ms = uptime_millis;
		st = SysTick->VAL;
	}
	uptime = ms * 1000 - st / ((SysTick->LOAD + 1) / 1000);

	buffer[0] = ((uptime >> 24) & 0xFF);
	buffer[1] = ((uptime >> 16) & 0xFF);
	buffer[2] = ((uptime >> 8) & 0xFF);
	buffer[3] = uptime & 0xFF;
}

/**
 * @brief Gets the current timestamp and stores it in the provided buffer.
 * @param buffer: Pointer to the buffer where the timestamp will be stored.
 */
void getTimestamp(uint8_t *buffer) {
	RTC_TimeTypeDef current_time;
	RTC_DateTypeDef current_date;

	HAL_RTC_GetTime(&hrtc, &current_time, RTC_FORMAT_BIN);
	HAL_RTC_GetDate(&hrtc, &current_date, RTC_FORMAT_BIN);
	uint32_t milliseconds = 1000000 - (current_time.SubSeconds * 100);

	buffer[0] = current_date.Year;				// 0-99
	buffer[1] = current_date.Month;				// 1-12
	buffer[2] = current_date.Date;				// 1-31
	buffer[3] = current_time.Hours;				// 0-23
	buffer[4] = current_time.Minutes;			// 0-59
	buffer[5] = current_time.Seconds;			// 0-59
	buffer[6] = ((milliseconds >> 24) & 0xFF);
	buffer[7] = ((milliseconds >> 16) & 0xFF);
	buffer[8] = ((milliseconds >> 8) & 0xFF);
	buffer[9] = milliseconds & 0xFF;
}

/**
 * @brief Samples PMT data and sends it as a packet.
 *
 * This function waits for a specific GPIO pin state, allocates memory for
 * PMT data, SPI data, and uptime information, and retrieves the current
 * uptime and PMT SPI data. It then constructs a data packet including synchronization
 * bytes, sequence information, and the retrieved data, and places the packet in
 * the message queue. Memory allocated for the data is subsequently freed.
 */
void sample_pmt() {
	while (HAL_GPIO_ReadPin(GPIOA, GPIO_PIN_8)) {
	}
	uint8_t *buffer = (uint8_t*) malloc(PMT_DATA_SIZE * sizeof(uint8_t));
	uint8_t *pmt_spi = (uint8_t*) malloc(2 * sizeof(uint8_t));
	uint8_t *uptime = (uint8_t*) malloc(UPTIME_SIZE * sizeof(uint8_t));

	get_uptime(uptime);

	receive_pmt_spi(pmt_spi);

	buffer[0] = PMT_SYNC;
	buffer[1] = PMT_SYNC;
	buffer[2] = ((pmt_seq & 0xFF00) >> 8);
	buffer[3] = (pmt_seq & 0xFF);
	buffer[4] = pmt_spi[0];
	buffer[5] = pmt_spi[1];
	buffer[6] = uptime[0];
	buffer[7] = uptime[1];
	buffer[8] = uptime[2];
	buffer[9] = uptime[3];

	packet_t pmt_packet = create_packet(buffer, PMT_DATA_SIZE);
	osMessageQueuePut(mid_MsgQueue, &pmt_packet, 0U, 0U);
	free(buffer);
	free(pmt_spi);
	free(uptime);
}

/**
 * @brief Samples ERPA data and sends it as a packet.
 *
 * This function waits for a specific GPIO pin state, allocates memory for
 * the ERPA data, retrieves uptime, SPI data, and ADC readings, and constructs
 * a data packet with synchronization bytes, sequence information, and the
 * collected data. The packet is then placed in the message queue, and the
 * allocated memory is freed.
 */
void sample_erpa() {
	while (HAL_GPIO_ReadPin(GPIOB, GPIO_PIN_11)) {
	}

	uint8_t *buffer = (uint8_t*) malloc(ERPA_DATA_SIZE * sizeof(uint8_t)); // Allocate memory for the buffer

	uint8_t *erpa_spi = (uint8_t*) malloc(2 * sizeof(uint8_t));
	uint16_t *erpa_adc = (uint16_t*) malloc(1 * sizeof(uint16_t));
	uint8_t *uptime = (uint8_t*) malloc(UPTIME_SIZE * sizeof(uint8_t));
	uint8_t sweep_step = -1;

	get_uptime(uptime);
	sweep_step = get_current_step();

	receive_erpa_spi(erpa_spi);
	receive_erpa_adc(erpa_adc);

	buffer[0] = ERPA_SYNC;
	buffer[1] = ERPA_SYNC;
	buffer[2] = ((erpa_seq >> 16) & 0xFF);
	buffer[3] = ((erpa_seq >> 8) & 0xFF);
	buffer[4] = erpa_seq & 0xFF;
	buffer[5] = sweep_step;
	buffer[6] = ((erpa_adc[0] & 0xFF00) >> 8);	// SWP Monitored MSB
	buffer[7] = (erpa_adc[0] & 0xFF);           // SWP Monitored LSB
	buffer[8] = erpa_spi[0];					// ERPA eADC MSB
	buffer[9] = erpa_spi[1];					// ERPA eADC LSB
	buffer[10] = uptime[0];
	buffer[11] = uptime[1];
	buffer[12] = uptime[2];
	buffer[13] = uptime[3];

	packet_t erpa_packet = create_packet(buffer, ERPA_DATA_SIZE);
	osMessageQueuePut(mid_MsgQueue, &erpa_packet, 0U, 0U);
	free(buffer);
	free(erpa_spi);
	free(erpa_adc);
	free(uptime);
}

/**
 * @brief Samples housekeeping data and sends it as a packet.
 *
 * This function allocates memory for the housekeeping data buffer, retrieves
 * and processes I2C readings, and updates the buffer with various system
 * metrics, including voltage readings and temperatures. It then constructs
 * a data packet with synchronization bytes, sequence information, and sampled
 * data, and places the packet in the message queue. The allocated memory is
 * subsequently freed.
 */
void sample_hk() {
	uint8_t *buffer = (uint8_t*) malloc(HK_DATA_SIZE * sizeof(uint8_t));
	uint8_t *timestamp = (uint8_t*) malloc(TIMESTAMP_SIZE * sizeof(uint8_t));
	uint8_t *uptime = (uint8_t*) malloc(UPTIME_SIZE * sizeof(uint8_t));

	get_uptime(uptime);
	getTimestamp(timestamp);

	buffer[0] = HK_SYNC;                     	// HK SYNC 0xCC MSB
	buffer[1] = HK_SYNC;                     	// HK SYNC 0xCC LSB
	buffer[2] = ((hk_seq & 0xFF00) >> 8);    	// HK SEQ # MSB
	buffer[3] = (hk_seq & 0xFF);             	// HK SEQ # LSB
	buffer[4] = ((rail_monitor[RAIL_vsense].data & 0xFF00) >> 8);		// HK vsense MSB
	buffer[5] = (rail_monitor[RAIL_vsense].data & 0xFF);				// HK vsense LSB
	buffer[6] = ((rail_monitor[RAIL_vrefint].data & 0xFF00) >> 8);		// HK vrefint MSB
	buffer[7] = (rail_monitor[RAIL_vrefint].data & 0xFF);				// HK vrefint LSB
	buffer[8] = ((rail_monitor[RAIL_TEMP1].data & 0xFF00) >> 8);	// HK TEMP1 MSB
	buffer[9] = (rail_monitor[RAIL_TEMP1].data & 0xFF);				// HK TEMP1 LSB
	buffer[10] = ((rail_monitor[RAIL_TEMP2].data & 0xFF00) >> 8);	// HK TEMP2 MSB
	buffer[11] = (rail_monitor[RAIL_TEMP2].data & 0xFF);			// HK TEMP2 LSB
	buffer[12] = ((rail_monitor[RAIL_TEMP3].data & 0xFF00) >> 8);	// HK TEMP3 MSB
	buffer[13] = (rail_monitor[RAIL_TEMP3].data & 0xFF);			// HK TEMP3 LSB
	buffer[14] = ((rail_monitor[RAIL_TEMP4].data & 0xFF00) >> 8);	// HK TEMP4 MSB
	buffer[15] = (rail_monitor[RAIL_TEMP4].data & 0xFF);			// HK TEMP4 LSB
	buffer[16] = ((rail_monitor[RAIL_busvmon].data & 0xFF00) >> 8);	// HK BUSvmon MSB
	buffer[17] = (rail_monitor[RAIL_busvmon].data & 0xFF);				// HK BUSvmon LSB
	buffer[18] = ((rail_monitor[RAIL_busimon].data & 0xFF00) >> 8);	// HK BUSimon MSB
	buffer[19] = (rail_monitor[RAIL_busimon].data & 0xFF);				// HK BUSimon LSB
	buffer[20] = ((rail_monitor[RAIL_2v5].data & 0xFF00) >> 8);		// HK 2v5mon MSB
	buffer[21] = (rail_monitor[RAIL_2v5].data & 0xFF);					// HK 2v5mon LSB
	buffer[22] = ((rail_monitor[RAIL_3v3].data & 0xFF00) >> 8);		// HK 3v3mon MSB
	buffer[23] = (rail_monitor[RAIL_3v3].data & 0xFF);					// HK 3v3mon LSB
	buffer[24] = ((rail_monitor[RAIL_5v].data & 0xFF00) >> 8);			// HK 5vmon MSB
	buffer[25] = (rail_monitor[RAIL_5v].data & 0xFF);					// HK 5vmon LSB
	buffer[26] = ((rail_monitor[RAIL_n3v3].data & 0xFF00) >> 8);		// HK n3v3mon MSB
	buffer[27] = (rail_monitor[RAIL_n3v3].data & 0xFF);				// HK n3v3mon LSB
	buffer[28] = ((rail_monitor[RAIL_n5v].data & 0xFF00) >> 8);		// HK n5vmon MSB
	buffer[29] = (rail_monitor[RAIL_n5v].data & 0xFF);					// HK n5vmon LSB
	buffer[30] = ((rail_monitor[RAIL_15v].data & 0xFF00) >> 8);		// HK 15vmon MSB
	buffer[31] = (rail_monitor[RAIL_15v].data & 0xFF);					// HK 15vmon LSB
	buffer[32] = ((rail_monitor[RAIL_5vref].data & 0xFF00) >> 8);		// HK 5vrefmon MSB
	buffer[33] = (rail_monitor[RAIL_5vref].data & 0xFF);				// HK 5vrefmon LSB
	buffer[34] = ((rail_monitor[RAIL_n200v].data & 0xFF00) >> 8);		// HK n150vmon MSB
	buffer[35] = (rail_monitor[RAIL_n200v].data & 0xFF);				// HK n150vmon LSB
	buffer[36] = ((rail_monitor[RAIL_n800v].data & 0xFF00) >> 8);		// HK n800vmon MSB
	buffer[37] = (rail_monitor[RAIL_n800v].data & 0xFF);				// HK n800vmon LSB
	buffer[38] = ((rail_monitor[RAIL_TMP1].data & 0xFF00) >> 8);  // TEMPURATURE 1 MSB
	buffer[39] = (rail_monitor[RAIL_TMP1].data & 0xFF);           // TEMPURATURE 1 LSB
	buffer[40] = timestamp[0];
	buffer[41] = timestamp[1];
	buffer[42] = timestamp[2];
	buffer[43] = timestamp[3];
	buffer[44] = timestamp[4];
	buffer[45] = timestamp[5];
	buffer[46] = timestamp[6];
	buffer[47] = timestamp[7];
	buffer[48] = timestamp[8];
	buffer[49] = timestamp[9];
	buffer[50] = uptime[0];
	buffer[51] = uptime[1];
	buffer[52] = uptime[2];
	buffer[53] = uptime[3];

	packet_t hk_packet = create_packet(buffer, HK_DATA_SIZE);
	osMessageQueuePut(mid_MsgQueue, &hk_packet, 0U, 0U);

	free(buffer);
	free(timestamp);
	free(uptime);
}

/* USER CODE END 4 */

/* USER CODE BEGIN Header_PMT_init */
// *********************************************************************************************************** RTOS TASK FUNCTIONS
/**
 * @brief  Function implementing the PMT_task thread.
 * @param  argument: Not used
 * @retval None
 */
/* USER CODE END Header_PMT_init */
void PMT_init(void *argument)
{
  /* USER CODE BEGIN 5 */
	/* Infinite loop */
	for (;;) {

		osEventFlagsWait(event_flags, PMT_FLAG_ID, osFlagsWaitAny,
		osWaitForever);
		if (PMT_ON) {
			sample_pmt();
			pmt_seq++;
		}
		osThreadYield();
	}
  /* USER CODE END 5 */
}

void ERPA_init(void *argument)
{
  /* USER CODE BEGIN ERPA_init */

	/* Infinite loop */
	for (;;) {
		osEventFlagsWait(event_flags, ERPA_FLAG_ID, osFlagsWaitAny,
		osWaitForever);
		if (ERPA_ON) {
			sample_erpa();
			erpa_seq++;
		}
		osThreadYield();
	}
  /* USER CODE END ERPA_init */
}

void HK_init(void *argument)
{
  /* USER CODE BEGIN HK_init */

	/* Infinite loop */
	for (;;) {
		osEventFlagsWait(event_flags, HK_FLAG_ID, osFlagsWaitAny,
		osWaitForever);
		if (HK_ON) {
			sample_hk();
			hk_seq++;
		}
		osThreadYield();
	}
  /* USER CODE END HK_init */
}

void GPIO_on_init(void *argument)
{
  /* USER CODE BEGIN GPIO_on_init */
	osThreadSuspend(GPIO_on_taskHandle);
	/* Infinite loop */
	for (;;) {

		// Enabling all voltages from SDN1 to 15V (inclusive)
		for (int i = 0; i < 7; i++) {
			HAL_GPIO_WritePin(gpios[i].gpio, gpios[i].pin, GPIO_PIN_SET);
			osDelay(100);
		}

		// Telling rail monitor which rails are now enabled
		for (int i = RAIL_2v5; i <= RAIL_15v; i++){
			rail_monitor[i].is_enabled = 1;
		}

		osThreadSuspend(GPIO_on_taskHandle);
	}
  /* USER CODE END GPIO_on_init */
}

void GPIO_off_init(void *argument)
{
  /* USER CODE BEGIN GPIO_off_init */
	osThreadSuspend(GPIO_off_taskHandle);
	/* Infinite loop */
	for (;;) {

		// Telling rail monitor which rails are now disabled
		for (int i = RAIL_15v; i >= RAIL_2v5; i--){
			rail_monitor[i].is_enabled = 0;
		}

		// Disabling all voltages from 15V to SDN1 (inclusive)
		for (int i = 6; i >= 0; i--) {
			HAL_GPIO_WritePin(gpios[i].gpio, gpios[i].pin, GPIO_PIN_RESET);
			osDelay(100);
		}

		osThreadSuspend(GPIO_off_taskHandle);
	}
  /* USER CODE END GPIO_off_init */
}

/* USER CODE BEGIN Header_UART_TX_init */
/**
 * @brief UART transmission initialization and processing task.
 *
 * This function continuously retrieves messages from the message queue,
 * stores them in a buffer, and sends the buffer data via UART using DMA.
 * It handles transmission completion by waiting for a flag and yields thread
 * control periodically. The function operates in an infinite loop, processing
 * and transmitting data as long as the task is running.
 *
 * @param argument Pointer to the argument passed to the thread (not used).
 */
/* USER CODE END Header_UART_TX_init */
void UART_TX_init(void *argument)
{
  /* USER CODE BEGIN UART_TX_init */
	static uint8_t tx_buffer[UART_TX_BUFFER_SIZE];

	uint32_t total_size = 0;
	osStatus_t status;

	while (1) {
		total_size = 0;
		// Retrieve all messages from the queue and store them in tx_buffer
		do {
			status = osMessageQueueGet(mid_MsgQueue, &msg, NULL, osWaitForever);
			if (status == osOK) {
				if ((total_size + msg.size) < UART_TX_BUFFER_SIZE) {
					memcpy(&tx_buffer[total_size], msg.array, msg.size);
					free(msg.array);
					total_size += msg.size;
					if (total_size >= (UART_TX_BUFFER_SIZE - HK_DATA_SIZE)) {
						break;
					}
				}
			}
		} while (osMessageQueueGetCount(mid_MsgQueue));

		if (total_size > 0) {
			HAL_UART_Transmit_DMA(&huart1, tx_buffer, total_size);

			// Wait for transmission to complete
			while (tx_flag == 0) {
				osThreadYield();
			}

			// Reset the flag
			tx_flag = 0;
		}

		// Yield thread control
		osThreadYield();
	}
  /* USER CODE END UART_TX_init */
}

void Voltage_Monitor_init(void *argument)
{
  /* USER CODE BEGIN Voltage_Monitor_init */
	/* Infinite loop */

	// TODO: Figure out how we should monitor busvmon, busimon, vsense, and vrefint
	for (;;) {
		osEventFlagsWait(event_flags, VOLTAGE_MONITOR_FLAG_ID, osFlagsWaitAny,
		osWaitForever);

		uint16_t *hk_adc1 = (uint16_t*) malloc(10 * sizeof(uint16_t));
		uint16_t *hk_adc3 = (uint16_t*) malloc(4 * sizeof(uint16_t));
		int16_t *hk_i2c = (int16_t*) malloc(4 * sizeof(int16_t));

		receive_hk_i2c(hk_i2c);
		receive_hk_adc1(hk_adc1);
		receive_hk_adc3(hk_adc3);

		rail_monitor[RAIL_vsense].data = hk_adc3[1];
		rail_monitor[RAIL_vrefint].data = hk_adc3[0];
		rail_monitor[RAIL_TEMP1].data = hk_i2c[0];
		rail_monitor[RAIL_TEMP2].data = hk_i2c[1];
		rail_monitor[RAIL_TEMP3].data = hk_i2c[2];
		rail_monitor[RAIL_TEMP4].data = hk_i2c[3];
		rail_monitor[RAIL_busvmon].data = hk_adc1[0];
		rail_monitor[RAIL_busimon].data = hk_adc1[1];
		rail_monitor[RAIL_2v5].data = hk_adc1[2];
		rail_monitor[RAIL_3v3].data = hk_adc3[3];
		rail_monitor[RAIL_5v].data = hk_adc1[6];
		rail_monitor[RAIL_n3v3].data = hk_adc1[3];
		rail_monitor[RAIL_n5v].data = hk_adc3[2];
		rail_monitor[RAIL_15v].data = hk_adc1[7];
		rail_monitor[RAIL_5vref].data = hk_adc1[8];
		rail_monitor[RAIL_n200v].data = hk_adc1[4];
		rail_monitor[RAIL_n800v].data = hk_adc1[5];
		rail_monitor[RAIL_TMP1].data = hk_adc1[9];

		// Iterate through all voltage rails
		for (int i = 0; i < NUM_VOLTAGE_RAILS; i++){
			if (rail_monitor[i].is_enabled){
				// If current rail is not in range...
				if (!in_range(rail_monitor[i].data, rail_monitor[i].min_voltage, rail_monitor[i].max_voltage)){
					// Increase that rails error count
					rail_monitor[i].error_count++;
					// If that rails' error count is at 3, proceed with error protocol for that rail
					if (rail_monitor[i].error_count == 3) {
						error_protocol(rail_monitor[i].name);
					}
				}
			}
		}

#ifdef FLIGHT_MODE

#endif

		free(hk_adc1);
		free(hk_adc3);
		free(hk_i2c);

		osThreadYield();
	}
  /* USER CODE END Voltage_Monitor_init */
}

void FLAG_init(void *argument)
{
  /* USER CODE BEGIN FLAG_init */
	/* Infinite loop */
	for (;;) {
		int current_flag = osEventFlagsGet(event_flags);

		if ((current_flag & STOP_FLAG) != 0) {
			osEventFlagsClear(event_flags, STOP_FLAG);
			enter_stop();
		}
		osDelay(1);
	}
  /* USER CODE END FLAG_init */
}

void Science_init(void *argument)
{
  /* USER CODE BEGIN Science_init */
	osThreadSuspend(Science_taskHandle);

  /* Infinite loop */
  for(;;)
  {
		// Enabling all voltages
		for (int i = 0; i < 9; i++) {
			HAL_GPIO_WritePin(gpios[i].gpio, gpios[i].pin, GPIO_PIN_SET);
			osDelay(200);
		}

		// Telling rail monitor which voltages are now enabled
		for (int i = RAIL_2v5; i <= RAIL_n800v; i++) {
			rail_monitor[i].is_enabled = 1;
		}

		__disable_irq();

		HAL_DAC_Start_DMA(&hdac1, DAC_CHANNEL_1, DAC_OUT, 32, DAC_ALIGN_12B_R);	// Enable auto sweep (doesn't start until ERPA timer is started)
		HK_ON = 1;
		HAL_TIM_OC_Start_IT(&htim2, TIM_CHANNEL_4);			// ERPA packet on
		ERPA_ON = 1;
		HAL_TIM_OC_Start_IT(&htim1, TIM_CHANNEL_1);				// PMT packet on
		PMT_ON = 1;

		osEventFlagsSet(event_flags, HK_FLAG_ID);
		osEventFlagsSet(event_flags, ERPA_FLAG_ID);
		osEventFlagsSet(event_flags, PMT_FLAG_ID);

		__enable_irq();

		osThreadSuspend(Science_taskHandle);
  }
  /* USER CODE END Science_init */
}

void Idle_init(void *argument)
{
  /* USER CODE BEGIN Idle_init */
	osThreadSuspend(Idle_taskHandle);

  /* Infinite loop */
  for(;;)
  {
		HAL_TIM_OC_Stop_IT(&htim1, TIM_CHANNEL_1);
		PMT_ON = 0;
		HAL_TIM_OC_Stop_IT(&htim2, TIM_CHANNEL_4);
		ERPA_ON = 0;
		HK_ON = 0;
		osDelay(100);

		// Telling rail monitor which voltages are now disabled
		for (int i = RAIL_n800v; i >= RAIL_2v5; i--) {
			rail_monitor[i].is_enabled = 0;
		}

		// Disabling all voltages
		for (int i = 8; i >= 0; i--) {
			HAL_GPIO_WritePin(gpios[i].gpio, gpios[i].pin, GPIO_PIN_RESET);
			osDelay(200);
		}

		osThreadSuspend(Idle_taskHandle);
  }
  /* USER CODE END Idle_init */
}

void HAL_TIM_PeriodElapsedCallback(TIM_HandleTypeDef *htim)
{
  if (htim->Instance == TIM6) {
    HAL_IncTick();
  }
}

void Error_Handler(void)
{
	__disable_irq();
	while (1) {
	}
}

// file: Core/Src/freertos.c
/* USER CODE BEGIN Header */
/**
 ******************************************************************************
 * File Name          : freertos.c
 * Description        : Code for freertos applications
 ******************************************************************************
 * @attention
 *
 * Copyright (c) 2024 STMicroelectronics.
 * All rights reserved.
 *
 * This software is licensed under terms that can be found in the LICENSE file
 * in the root directory of this software component.
 * If no LICENSE file comes with this software, it is provided AS-IS.
 *
 ******************************************************************************
 */
/* USER CODE END Header */

#include "FreeRTOS.h"
#include "task.h"
#include "main.h"

/* Hook prototypes */
void vApplicationTickHook(void);

/* USER CODE BEGIN 3 */
void vApplicationTickHook( void )
{
   /* This function will be called by each tick interrupt if
   configUSE_TICK_HOOK is set to 1 in FreeRTOSConfig.h. User code can be
   added here, but the tick hook is called from an interrupt context, so
   code must not attempt to block, and only the interrupt safe FreeRTOS API
   functions can be used (those that end in FromISR()). */
	uptime_millis++;
}
/* USER CODE END 3 */
